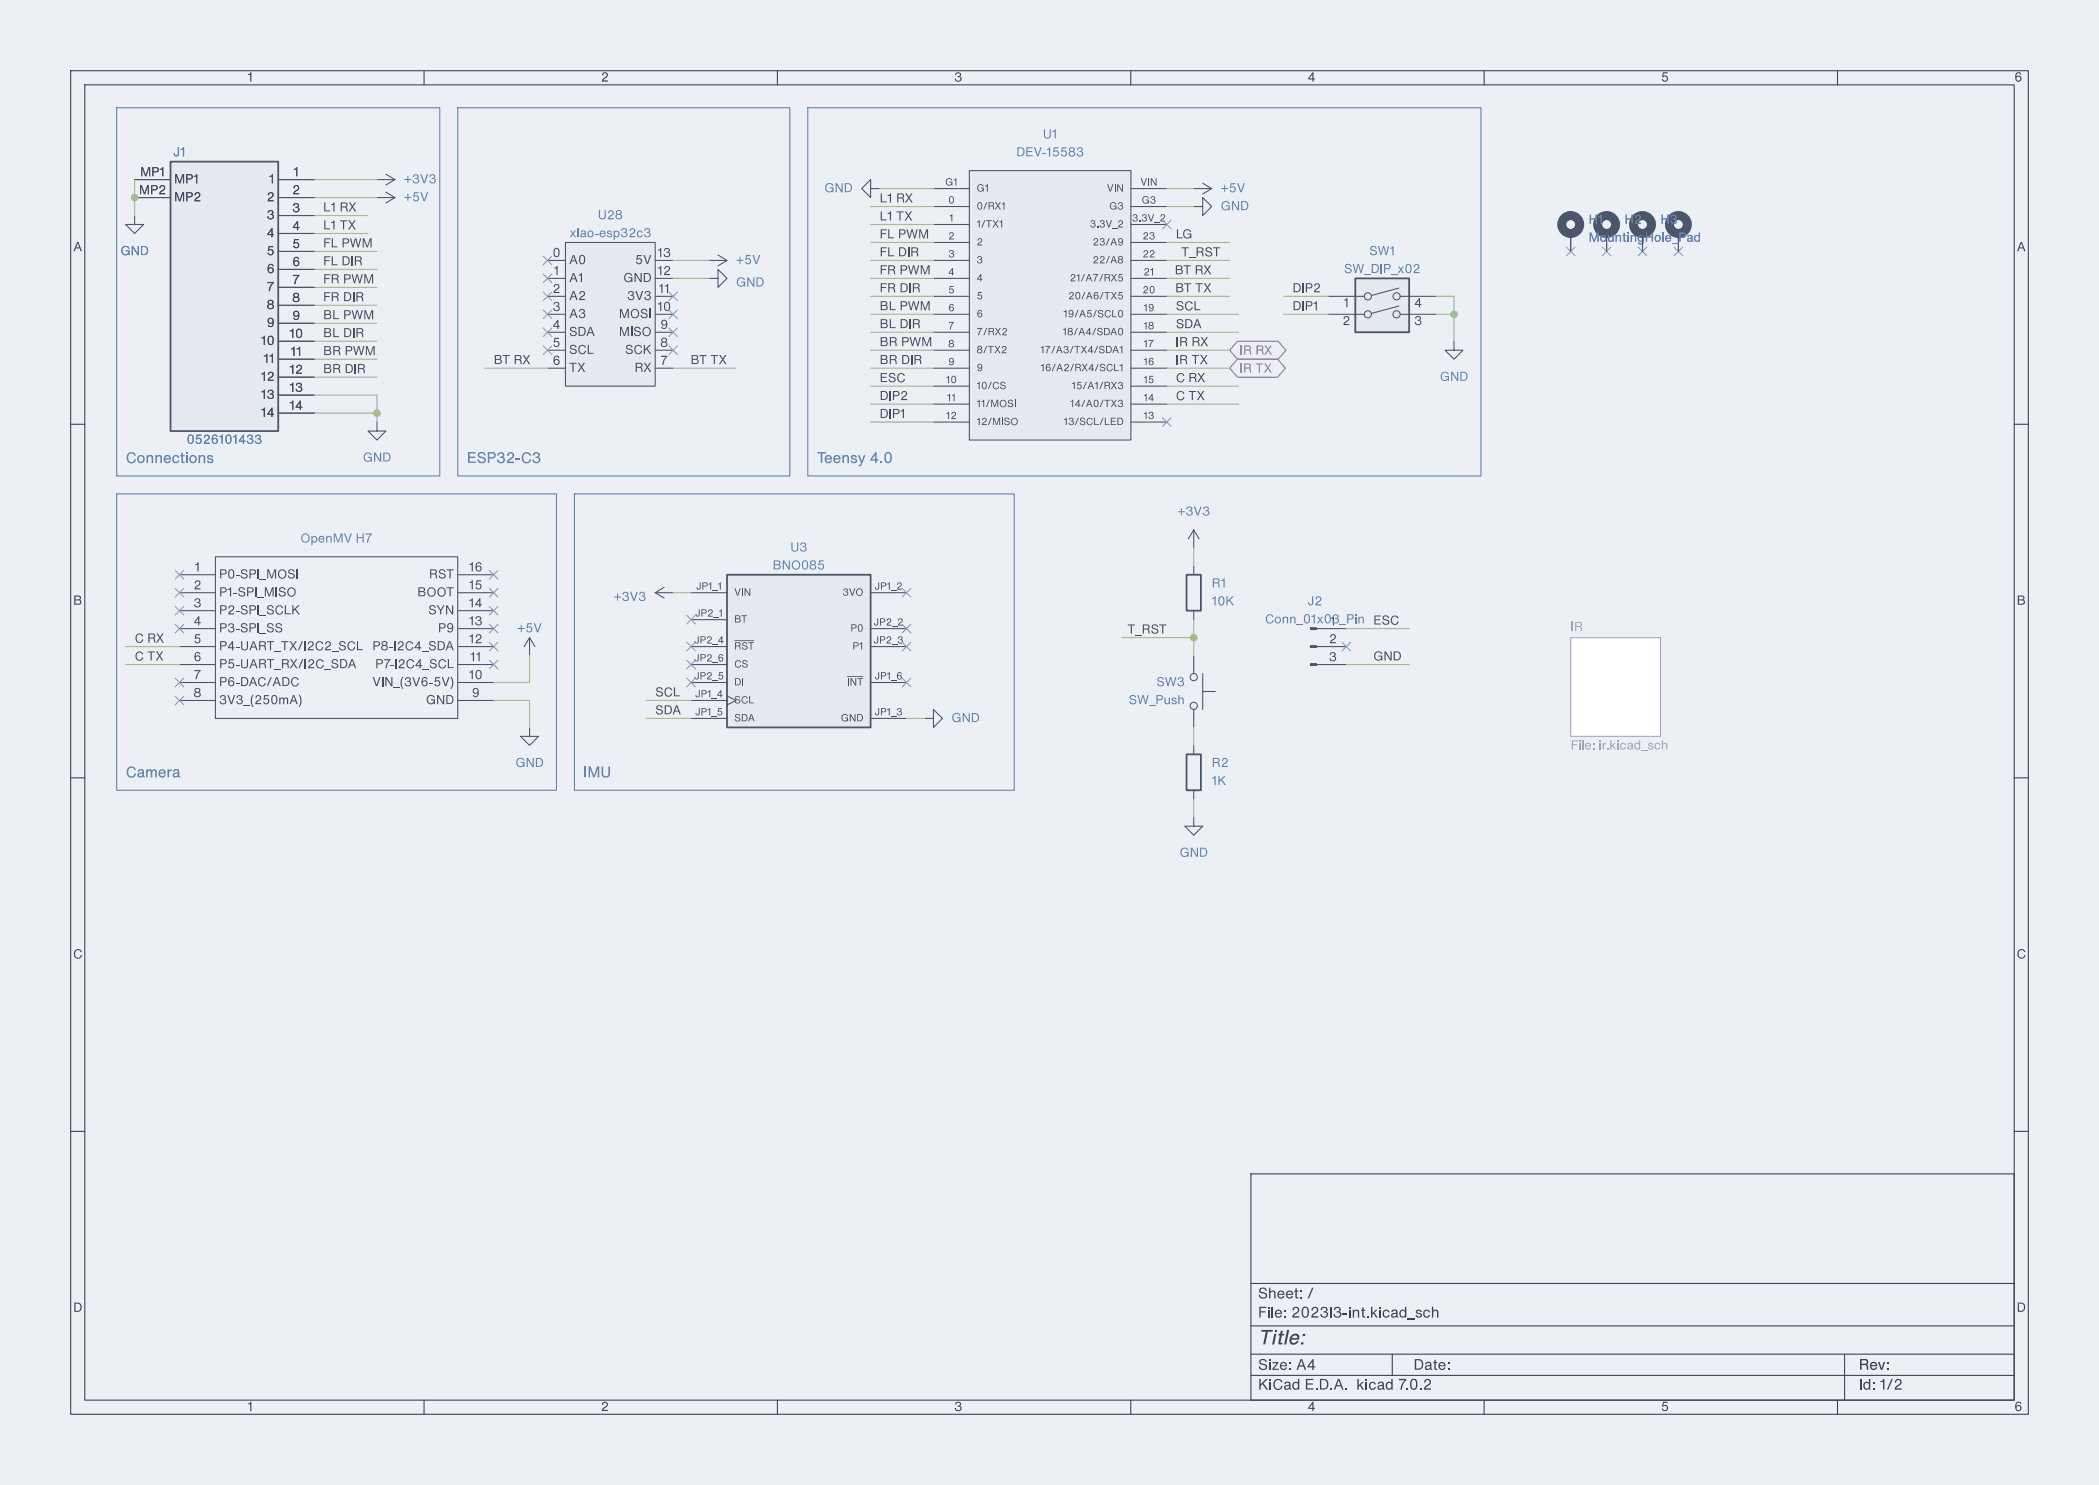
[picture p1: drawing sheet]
<svg xmlns="http://www.w3.org/2000/svg" width="297mm" height="210mm" viewBox="0 0 297 210" stroke-linecap="round" stroke-linejoin="round" font-family="sans-serif">
<defs><g id="words">
<text font-size="2.8" fill="#3b4252" x="178" y="190.8">Title:</text>
<g font-size="2.1" fill="#5e81ac">
<text x="17.8" y="65.7">Connections</text>
<text x="66" y="65.7">ESP32-C3</text>
<text x="115.6" y="65.7">Teensy4.0</text>
<text x="17.8" y="110.2">Camera</text>
<text x="82.5" y="110.2">IMU</text>
</g>
<g font-size="2.1" fill="#3b4252">
<text x="178" y="184.1">Sheet: /</text>
<text x="178" y="186.8">File: 2023l3-int.kicad_sch</text>
<text x="178" y="197">KiCad E.D.A. kicad 7.0.2</text>
<text x="178" y="194.2">Size: A4</text>
<text x="200" y="194.2">Date:</text>
<text x="263" y="194.2">Rev:</text>
<text x="263" y="197">Id: 1/2</text>
</g>
<g font-size="1.8" fill="#3b4252">
<text x="35" y="12">1</text>
<text x="85" y="12">2</text>
<text x="135" y="12">3</text>
<text x="185" y="12">4</text>
<text x="235" y="12">5</text>
<text x="285" y="12">6</text>
<text x="10.3" y="36">A</text>
<text x="285.4" y="36">A</text>
<text x="10.3" y="86">B</text>
<text x="285.3" y="86">B</text>
<text x="10.3" y="136">C</text>
<text x="285.3" y="136">C</text>
<text x="10.4" y="186">D</text>
<text x="285.4" y="186">D</text>
<text x="35" y="200">1</text>
<text x="85" y="200">2</text>
<text x="135" y="200">3</text>
<text x="185" y="200">4</text>
<text x="235" y="200">5</text>
<text x="285" y="200">6</text>
</g>
<g font-size="1.8" fill="#5e81ac">
<text x="24.5" y="22.5">J1</text>
<text x="143.8" y="22.5">DEV-15583</text>
<text x="147.6" y="20">U1</text>
<text x="57.1" y="26.3">+3V3</text>
<text x="57.1" y="28.9">+5V</text>
<text x="116.6" y="27.6">GND</text>
<text x="172.7" y="27.6">+5V</text>
<text x="80.6" y="34">xiao-esp32c3</text>
<text x="84.6" y="31.4">U28</text>
<text x="172.7" y="30.2">GND</text>
<text x="224.8" y="32.1">H1</text>
<text x="229.9" y="32.1">H2</text>
<text x="234.9" y="32.1">H3</text>
<text x="17" y="36.5">GND</text>
<text x="104.1" y="41">GND</text>
<text x="104.1" y="37.8">+5V</text>
<text x="190.2" y="39">SW_DIP_x02</text>
<text x="193.7" y="36.5">SW1</text>
<text x="203.7" y="54.3">GND</text>
<text x="26.4" y="63.2">0526101433</text>
<text x="51.3" y="65.7">GND</text>
<text x="42.5" y="77.1">OpenMV H7</text>
<text x="166.6" y="73.3">+3V3</text>
<text x="109.3" y="81">BNO085</text>
<text x="111.8" y="78.4">U3</text>
<text x="171.4" y="83.5">R1</text>
<text x="73.2" y="89.8">+5V</text>
<text x="86.8" y="85.4">+3V3</text>
<text x="171.4" y="86">10K</text>
<text x="179" y="88.6">Conn_01x03_Pin</text>
<text x="185" y="86">J2</text>
<text x="159.7" y="100">SW_Push</text>
<text x="163.6" y="97.5">SW3</text>
<text x="134.6" y="102.5">GND</text>
<text x="72.9" y="108.9">GND</text>
<text x="171.4" y="108.9">R2</text>
<text x="171.4" y="111.4">1K</text>
<text x="166.9" y="121.6">GND</text>
</g>
<g font-size="1.8" fill="#434c5e">
<text x="19.7" y="27.7">MP2</text>
<text x="19.8" y="25.1">MP1</text>
<text x="24.6" y="26.3">MP1</text>
<text x="24.6" y="28.9">MP2</text>
<text x="37.7" y="28.9">2</text>
<text x="38.1" y="26.3">1</text>
<text x="41.3" y="27.7">2</text>
<text x="41.5" y="25.1">1</text>
<text x="124.5" y="28.9">L1 RX</text>
<text x="37.7" y="31.4">3</text>
<text x="37.7" y="34">4</text>
<text x="41.3" y="30.2">3</text>
<text x="41.3" y="32.8">4</text>
<text x="41.3" y="35.3">5</text>
<text x="45.7" y="32.7">L1 TX</text>
<text x="45.7" y="30.1">L1 RX</text>
<text x="45.7" y="35.2">FL PWM</text>
<text x="124.5" y="33.9">FL PWM</text>
<text x="124.5" y="31.4">L1 TX</text>
<text x="166.4" y="33.9">LG</text>
<text x="37.7" y="36.5">5</text>
<text x="37.7" y="39">6</text>
<text x="37.7" y="41.6">7</text>
<text x="41.3" y="37.8">6</text>
<text x="41.3" y="40.4">7</text>
<text x="45.7" y="37.8">FL DIR</text>
<text x="45.7" y="40.3">FR PWM</text>
<text x="78.2" y="36.6">0</text>
<text x="78.2" y="41.7">2</text>
<text x="78.3" y="39.1">1</text>
<text x="80.5" y="37.8">A0</text>
<text x="80.5" y="40.3">A1</text>
<text x="88.2" y="40.3">GND</text>
<text x="89.9" y="37.8">5V</text>
<text x="93" y="39.1">12</text>
<text x="93" y="36.6">13</text>
<text x="93.2" y="41.7">11</text>
<text x="124.5" y="41.6">FR DIR</text>
<text x="124.5" y="36.5">FL DIR</text>
<text x="124.5" y="39">FR PWM</text>
<text x="166.2" y="39">BT RX</text>
<text x="166.3" y="41.6">BT TX</text>
<text x="167.1" y="36.5">T_RST</text>
<text x="182.9" y="41.6">DIP2</text>
<text x="37.7" y="44.1">8</text>
<text x="37.7" y="46.7">9</text>
<text x="41.3" y="42.9">8</text>
<text x="41.3" y="45.5">9</text>
<text x="45.7" y="42.8">FR DIR</text>
<text x="45.7" y="45.4">BL PWM</text>
<text x="45.7" y="47.9">BL DIR</text>
<text x="78.2" y="44.2">3</text>
<text x="78.2" y="46.7">4</text>
<text x="80.5" y="42.9">A2</text>
<text x="80.5" y="45.4">A3</text>
<text x="80.5" y="47.9">SDA</text>
<text x="87.6" y="45.4">MOSI</text>
<text x="87.6" y="47.9">MISO</text>
<text x="88.7" y="42.9">3V3</text>
<text x="93" y="44.2">10</text>
<text x="93.4" y="46.7">9</text>
<text x="124.5" y="44.1">BL PWM</text>
<text x="124.5" y="46.6">BL DIR</text>
<text x="166.4" y="46.6">SDA</text>
<text x="166.4" y="44.1">SCL</text>
<text x="182.9" y="44.1">DIP1</text>
<text x="36.9" y="49.2">10</text>
<text x="37.3" y="51.7">11</text>
<text x="40.9" y="48">10</text>
<text x="40.9" y="53.1">12</text>
<text x="41.1" y="50.5">11</text>
<text x="45.7" y="53">BR DIR</text>
<text x="45.7" y="50.5">BR PWM</text>
<text x="69.8" y="51.7">BT RX</text>
<text x="78.2" y="49.3">5</text>
<text x="78.2" y="51.8">6</text>
<text x="80.5" y="50.5">SCL</text>
<text x="80.5" y="53">TX</text>
<text x="88.4" y="50.5">SCK</text>
<text x="89.8" y="53">RX</text>
<text x="93.4" y="51.8">7</text>
<text x="93.4" y="49.3">8</text>
<text x="97.7" y="51.7">BT TX</text>
<text x="124.5" y="51.7">BR DIR</text>
<text x="124.5" y="49.2">BR PWM</text>
<text x="166.4" y="51.7">IR TX</text>
<text x="166.4" y="49.2">IR RX</text>
<text x="36.9" y="54.3">12</text>
<text x="36.9" y="56.8">13</text>
<text x="36.9" y="59.4">14</text>
<text x="40.9" y="55.6">13</text>
<text x="40.9" y="58.2">14</text>
<text x="124.5" y="56.8">DIP2</text>
<text x="124.5" y="54.3">ESC</text>
<text x="124.5" y="59.3">DIP1</text>
<text x="166.4" y="54.3">C RX</text>
<text x="166.4" y="56.8">C TX</text>
<text x="27.4" y="83.6">2</text>
<text x="27.5" y="81">1</text>
<text x="31" y="82.2">P0-SPI_MOSI</text>
<text x="60.7" y="82.2">RST</text>
<text x="66.3" y="83.6">15</text>
<text x="66.3" y="81">16</text>
<text x="27.4" y="86.1">3</text>
<text x="27.4" y="88.6">4</text>
<text x="31" y="84.8">P1-SPI_MISO</text>
<text x="31" y="87.3">P2-SPI_SCLK</text>
<text x="31" y="89.8">P3-SPI_SS</text>
<text x="59" y="84.8">BOOT</text>
<text x="60.6" y="87.3">SYN</text>
<text x="62" y="89.8">P9</text>
<text x="66.3" y="88.6">13</text>
<text x="66.3" y="86.1">14</text>
<text x="159.5" y="89.8">T_RST</text>
<text x="188.2" y="88.6">1</text>
<text x="194.3" y="88.6">ESC</text>
<text x="19" y="93.6">C TX</text>
<text x="19" y="91.1">C RX</text>
<text x="27.4" y="91.2">5</text>
<text x="27.4" y="93.7">6</text>
<text x="31" y="92.4">P4-UART_TX/I2C2_SCL</text>
<text x="31" y="94.9">P5-UART_RX/I2C_SDA</text>
<text x="52.7" y="92.4">P8-I2C4_SDA</text>
<text x="53.1" y="94.9">P7-I2C4_SCL</text>
<text x="66.3" y="91.2">12</text>
<text x="66.5" y="93.7">11</text>
<text x="188" y="91.2">2</text>
<text x="188" y="93.7">3</text>
<text x="194.3" y="93.6">GND</text>
<text x="27.4" y="96.3">7</text>
<text x="27.4" y="98.8">8</text>
<text x="31" y="97.5">P6-DAC/ADC</text>
<text x="31" y="100">3V3_(250mA)</text>
<text x="52.7" y="97.5">VIN_(3V6-5V)</text>
<text x="60.3" y="100">GND</text>
<text x="66.3" y="96.3">10</text>
<text x="66.7" y="98.8">9</text>
<text x="92.7" y="101.3">SDA</text>
<text x="92.7" y="98.7">SCL</text>
</g>
<text font-size="1.8" fill="#4c566a" x="224.8" y="34.6">MountingHole_Pad</text>
<g font-size="1.8" fill="#bf616a">
<text x="175.4" y="50.6">IR RX</text>
<text x="175.4" y="53.1">IR TX</text>
</g>
<g font-size="1.8" fill="#b48ead">
<text x="222.2" y="89.5">IR</text>
<text x="222.2" y="106.6">File: ir.kicad_sch</text>
</g>
<g font-size="1.4" fill="#434c5e">
<text x="133.7" y="26.4">G1</text>
<text x="134.2" y="29">0</text>
<text x="138.2" y="27.4">G1</text>
<text x="138.2" y="30">0/RX1</text>
<text x="156.6" y="27.4">VIN</text>
<text x="156.9" y="30">G3</text>
<text x="161.4" y="26.4">VIN</text>
<text x="161.5" y="29">G3</text>
<text x="134.2" y="34">2</text>
<text x="134.3" y="31.5">1</text>
<text x="138.2" y="35">2</text>
<text x="138.2" y="32.5">1/TX1</text>
<text x="154.2" y="32.5">3.3V_2</text>
<text x="154.6" y="35">23/A9</text>
<text x="160.2" y="31.5">3.3V_2</text>
<text x="161.6" y="34">23</text>
<text x="134.2" y="36.6">3</text>
<text x="134.2" y="39.1">4</text>
<text x="134.2" y="41.7">5</text>
<text x="138.2" y="37.6">3</text>
<text x="138.2" y="40.1">4</text>
<text x="151.4" y="40.1">21/A7/RX5</text>
<text x="154.6" y="37.6">22/A8</text>
<text x="161.6" y="41.7">20</text>
<text x="161.6" y="36.6">22</text>
<text x="161.8" y="39.1">21</text>
<text x="134.2" y="44.2">6</text>
<text x="134.2" y="46.7">7</text>
<text x="138.2" y="42.7">5</text>
<text x="138.2" y="45.2">6</text>
<text x="138.2" y="47.7">7/RX2</text>
<text x="150.3" y="47.7">18/A4/SDA0</text>
<text x="150.5" y="45.2">19/A5/SCL0</text>
<text x="151.1" y="42.7">20/A6/TX5</text>
<text x="161.8" y="46.7">18</text>
<text x="161.8" y="44.2">19</text>
<text x="134.2" y="51.8">9</text>
<text x="134.2" y="49.3">8</text>
<text x="138.2" y="52.8">9</text>
<text x="138.2" y="50.3">8/TX2</text>
<text x="147.2" y="50.3">17/A3/TX4/SDA1</text>
<text x="147.2" y="52.8">16/A2/RX4/SCL1</text>
<text x="161.8" y="51.8">16</text>
<text x="161.8" y="49.3">17</text>
<text x="133.8" y="54.4">10</text>
<text x="133.8" y="59.4">12</text>
<text x="134" y="56.9">11</text>
<text x="138.2" y="55.4">10/CS</text>
<text x="138.2" y="57.9">11/MOSI</text>
<text x="151.4" y="57.9">14/A0/TX3</text>
<text x="151.6" y="55.4">15/A1/RX3</text>
<text x="161.8" y="59.4">13</text>
<text x="161.8" y="56.9">14</text>
<text x="161.8" y="54.4">15</text>
<text x="138.2" y="60.4">12/MISO</text>
<text x="150.5" y="60.4">13/SCL/LED</text>
<text x="98.5" y="83.6">JP1_1</text>
<text x="123.7" y="83.6">JP1_2</text>
<text x="98.3" y="87.4">JP2_1</text>
<text x="103.9" y="84.6">VIN</text>
<text x="103.9" y="88.4">BT</text>
<text x="119.2" y="84.6">3VO</text>
<text x="120.3" y="89.7">P0</text>
<text x="123.6" y="88.6">JP2_2</text>
<text x="98.2" y="91.2">JP2_4</text>
<text x="98.2" y="93.7">JP2_6</text>
<text x="103.9" y="94.7">CS</text>
<text x="120.6" y="92.2">P1</text>
<text x="123.6" y="91.2">JP2_3</text>
<text x="98.2" y="96.3">JP2_5</text>
<text x="98.3" y="98.8">JP1_4</text>
<text x="98.3" y="101.3">JP1_5</text>
<text x="103.9" y="99.8">SCL</text>
<text x="103.9" y="97.3">DI</text>
<text x="123.7" y="101.3">JP1_3</text>
<text x="123.7" y="96.3">JP1_6</text>
<text x="103.9" y="102.4">SDA</text>
<text x="119" y="102.4">GND</text>
</g>
</g></defs>
<path d="M0 0h297v210h-297z" fill="#eceff4" stroke="#eceff4" stroke-width=".14"/>
<g fill="none" stroke="#3b4252" stroke-width=".15">
<path d="M10 10h277v190h-277zM12 12h273v186h-273zM60 10v2M110 10v2M160 10v2M210 10v2M260 10v2M10 60h2M285 60h2M10 110h2M285 110h2M10 160h2"/>
<path d="M285 160h2M177 166h108v32h-108zM60 198v2M110 198v2M160 198v2M177 194.5h108M177 191.5h108M177 187.5h108M210 198v2M260 198v2"/>
</g>
<g fill="#3b4252">
<path d="M201.5 185.3l.4-.1 .4 .2v.2h-.1l-.1-.2h-.3l-.1 .1-.1 .2v.3l.2 .2h.2l.2-.3h.1l-.2 .4h-.3l-.3-.2-.1-.4z"/>
<path d="M202.6 184.8h.2v.6l.4-.2 .3 .2v.9h-.2v-.8l-.2-.1-.3 .2v.7h-.2z"/>
</g>
<path d="M177 181.5h108M197 191.5v3M261 191.5v6.5" fill="none" stroke="#3b4252" stroke-width=".15"/>
<path d="M222.2 90.2h12.7v13.9h-12.7z" fill="#fff" stroke="#fff" stroke-width=".14"/>
<path d="M222.2 90.2h12.7v13.9h-12.7z" fill="none" stroke="#b48ead" stroke-width=".15"/>
<g fill="#b48ead">
<path d="M222.4 104.7h.9v.1h-.7v.4h.6v.2h-.6v.6h-.2z"/>
<path d="M223.4 104.7h.2v.2h-.2z"/>
<path d="M223.9 104.7h.1v1.3h-.1z"/>
<path d="M226.3 104.7h.2v.2h-.2z"/>
<path d="M227.9 104.7h.1v.8l.4-.4h.2l-.3 .3 .4 .6h-.2l-.3-.5-.2 .1v.4h-.1z"/>
<path d="M228.9 104.7h.1v.2h-.1z"/>
<path d="M231.4 105.1l.3-.1 .2 .2v-.5h.2v1.3h-.2v-.2l-.2 .2-.3-.1-.2-.4h.2l.1 .3 .1 .1 .2-.1 .1-.3v-.2l-.2-.1-.2 .1-.1 .2h-.2z"/>
<path d="M235.1 104.7h.2v.5l.3-.2 .3 .2v.8h-.1v-.7l-.2-.1-.3 .1v.7h-.2z"/>
</g>
<path d="M137.2 24.1h22.8v38.1h-22.8z" fill="#e5e9f0" stroke="#e5e9f0" stroke-width=".14"/>
<g fill="none" stroke="#4c566a" stroke-width=".15">
<path d="M132.1 34.3h5.1M132.1 36.8h5.1M132.1 31.8h5.1M132.1 39.4h5.1M132.1 26.7h5.1M132.1 29.2h5.1M137.2 24.1h22.8v38.1h-22.8zM160 31.8h5.1M160 26.7h5.1M160 29.2h5.1M132.1 41.9h5.1M132.1 44.5h5.1"/>
<path d="M132.1 52.1h5.1M132.1 54.6h5.1M132.1 57.2h5.1M132.1 59.7h5.1M160 59.7h5.1"/>
</g>
<path d="M158.1 59.1h.5l.2 .1 .1 .5-.2 .3-.6 .1v-.9h.1v.8l.5-.1 .1-.3-.1-.3-.6-.1z" fill="#434c5e"/>
<path d="M160 57.2h5.1" fill="none" stroke="#4c566a" stroke-width=".15"/>
<path d="M158.3 56.6l.3-.1 .2 .2 .1 .2-.2 .1 .2 .1v.2l-.2 .2-.3 .1-.2-.2v-.2h.1l.2 .3 .2-.1 .1-.1-.1-.2h-.2v-.1l.2-.1v-.2h-.2l-.2 .1h-.1z" fill="#434c5e"/>
<path d="M160 54.6h5.1" fill="none" stroke="#4c566a" stroke-width=".15"/>
<path d="M158.3 54.1l.3-.1 .2 .1 .1 .2-.2 .2 .2 .1v.2l-.2 .2h-.3l-.2-.1v-.2h.1l.2 .2h.2l.1-.1-.1-.2-.2-.1v-.1h.2v-.2l-.2-.1-.2 .2h-.1z" fill="#434c5e"/>
<path d="M160 52.1h5.1" fill="none" stroke="#4c566a" stroke-width=".15"/>
<g fill="#434c5e">
<path d="M157.6 51.5h.2v.9h.5v.1h-.7z"/>
<path d="M158.4 51.6l.4-.1v1h-.1v-.8h-.3z"/>
</g>
<path d="M160 49.5h5.1" fill="none" stroke="#4c566a" stroke-width=".15"/>
<g fill="#434c5e">
<path d="M157.8 48.9h.1l.4 1h-.1l-.1-.3h-.5l-.1 .3h-.1l.2-.4h.4l-.1-.5-.2 .5h-.1z"/>
<path d="M158.4 49.1l.4-.2v1.1h-.1v-.8h-.3z"/>
</g>
<path d="M160 47h5.1" fill="none" stroke="#4c566a" stroke-width=".15"/>
<path d="M158.3 46.4h.3l.3 .2v.5l-.2 .3-.4-.1-.1-.4h.1l.1 .4h.3l.1-.3-.1-.4-.1-.1h-.1l-.2 .4h-.1z" fill="#434c5e"/>
<path d="M160 44.5h5.1" fill="none" stroke="#4c566a" stroke-width=".15"/>
<path d="M158.3 43.9l.3-.1 .3 .2v.6l-.2 .3-.4-.1-.1-.4h.1l.1 .3 .3 .1 .1-.3-.1-.4-.2-.1-.2 .4h-.1z" fill="#434c5e"/>
<path d="M160 41.9h5.1" fill="none" stroke="#4c566a" stroke-width=".15"/>
<path d="M158.3 41.3h.5v.1h-.4v.3h.2l.3 .1v.3l-.2 .2h-.3l-.2-.2h.1l.1 .1h.2l.2-.1-.2-.3h-.4z" fill="#434c5e"/>
<path d="M160 39.4h5.1" fill="none" stroke="#4c566a" stroke-width=".15"/>
<path d="M158.3 38.8h.5v.1h-.4v.3l.2-.1 .3 .2v.3l-.2 .2h-.3l-.2-.2v-.1h.1l.1 .2h.2l.2-.2-.2-.3-.4 .1z" fill="#434c5e"/>
<path d="M160 36.8h5.1" fill="none" stroke="#4c566a" stroke-width=".15"/>
<path d="M158.3 36.3l.3-.1 .2 .1 .1 .3-.2 .1 .2 .3-.1 .2-.4 .1-.2-.2v-.1l.3 .2 .3-.2-.1-.2h-.1l-.4 .2 .2-.3-.2-.2 .3 .1 .2-.1v-.1l-.1-.1-.4 .2z" fill="#434c5e"/>
<path d="M160 34.3h5.1" fill="none" stroke="#4c566a" stroke-width=".15"/>
<path d="M158.3 33.8l.3-.1 .3 .2v.5l-.2 .3h-.3l-.2-.2 .4 .1 .2-.4-.4 .1-.2-.3 .4 .2 .1-.1v-.2l-.2-.1-.2 .2h-.1z" fill="#434c5e"/>
<path d="M132.1 47h5.1M132.1 49.5h5.1" fill="none" stroke="#4c566a" stroke-width=".15"/>
<path d="M141.9 49l.3-.1 .2 .2v.3l-.5 .4h.5v.2h-.6v-.3l.5-.5-.1-.1-.1-.1-.2 .1v.2h-.1z" fill="#434c5e"/>
<g fill="none" stroke="#4c566a" stroke-width=".15">
<path d="M19 30.5v1.3h1.3l-1.3 1.2-1.2-1.2h1.2M19 25.4h5.1M19 27.9h5.1M39.4 25.4h5M39.4 27.9h5M39.4 30.5h5M39.4 33h5M39.4 35.6h5M39.4 38.1h5M53.3 25.4h2.6M53.3 27.9h2.6M54.6 24.6l1.3 .8"/>
<path d="M54.6 27.2l1.3 .7M55.9 25.4l-1.3 .8M55.9 27.9l-1.3 .8M100.3 39.4h1.3v-1.3l1.3 1.3-1.3 1.2v-1.2M39.4 48.3h5M39.4 50.8h5M39.4 53.3h5M39.4 55.9h5M39.4 58.4h5M39.4 40.6h5M39.4 43.2h5M39.4 45.7h5"/>
<path d="M168.9 74.9l.8 1.3M168.9 74.9v2.6M168.9 74.9l-.8 1.3M74.9 90.2l-.7 1.2M74.9 90.2v2.5M74.9 90.2l.8 1.2M92.7 83.8l1.3 .8M92.7 83.8h2.5M94 83.1l-1.3 .7M186.3 94h4.2M186.3 91.4h4.2M186.7 88.9h3.8"/>
<path d="M168.9 115.6v1.2h-1.3l1.3 1.3 1.3-1.3h-1.3"/>
</g>
<circle cx="237.5" cy="31.7" r="1.27" fill="none" stroke="#4c566a" stroke-width="1.3"/>
<g fill="#4c566a" stroke="#4c566a" stroke-width=".15">
<path d="M185.4 93.9h.9v.2h-.9z"/>
<path d="M185.4 91.3h.9v.3h-.9z"/>
</g>
<path d="M24.1 22.9h15.3v38.1h-15.3z" fill="#e5e9f0" stroke="#e5e9f0" stroke-width=".14"/>
<path d="M24.1 22.9h15.3v38.1h-15.3z" fill="none" stroke="#4c566a" stroke-width=".25"/>
<path d="M36.2 61.6l.4-.1 .3 .1v.3l-.1 .2 .1 .1 .1 .2-.2 .3-.4 .1-.3-.2v-.3h.1l.1 .3h.2h.2l.1-.2-.1-.2-.3-.1v-.1l.3-.1v-.2l-.3-.1-.1 .3h-.2z" fill="#5e81ac"/>
<path d="M102.9 81.3h20.3v21.6h-20.3z" fill="#e5e9f0" stroke="#e5e9f0" stroke-width=".14"/>
<path d="M102.9 81.3h20.3v21.6h-20.3z" fill="none" stroke="#4c566a" stroke-width=".25"/>
<path d="M97.8 83.8h5.1M97.8 99.1h5.1M102.9 98.4l1.2 .7-1.2 .6M123.2 83.8h5.1M123.2 96.5h5.1M97.8 101.6h5.1M123.2 101.6h5.1" fill="none" stroke="#4c566a" stroke-width=".15"/>
<g fill="#434c5e">
<path d="M120 95.9h.1v1h-.1z"/>
<path d="M120.3 95.9h.2l.5 .9v-.9h.2v1h-.2l-.5-.8v.8h-.2z"/>
<path d="M121.3 95.9h.8v.1h-.3v.9h-.2v-.9h-.3z"/>
<path d="M119.9 95.6l2.3 .1h-2.3z"/>
</g>
<path d="M97.8 87.6h5.1M97.8 91.4h5.1M123.2 88.9h5.1M123.2 91.4h5.1" fill="none" stroke="#4c566a" stroke-width=".15"/>
<g fill="#434c5e">
<path d="M104 90.8h.5l.2 .1 .1 .3-.2 .1 .2 .2v.4h-.1l-.1-.4-.1-.1h-.4v.5h-.1v-1h.1v.4h.4l.2-.2-.1-.1-.6-.1z"/>
<path d="M105.1 90.9l.3-.1 .3 .2v.1l-.3-.2-.3 .2 .1 .1 .5 .2 .1 .2-.1 .2-.4 .1-.3-.2v-.2h.1l.1 .2 .1 .1 .3-.1 .1-.1-.1-.2-.5-.1z"/>
<path d="M105.9 90.8h.8v.1h-.4v1h-.1v-1h-.3z"/>
<path d="M103.9 90.6h2.8l-2.8 .1z"/>
</g>
<g fill="none" stroke="#4c566a" stroke-width=".15">
<path d="M77.5 36.8h2.5M77.5 39.4h2.5M80 34.3h12.7v20.3h-12.7zM100.3 36.8h2.6M101.6 36.1l1.3 .7M102.9 36.8l-1.3 .8M77.5 41.9h2.5M77.5 44.5h2.5M77.5 47h2.5M77.5 49.5h2.5M77.5 52.1h2.5M92.7 41.9h2.5"/>
<path d="M92.7 47h2.5M92.7 49.5h2.5M92.7 52.1h2.5M97.8 96.5h5.1M97.8 94h5.1M130.8 101.6h1.3v-1.3l1.2 1.3-1.2 1.3v-1.3"/>
</g>
<path d="M80 34.3h12.7v20.3h-12.7z" fill="#e5e9f0" stroke="#e5e9f0" stroke-width=".14"/>
<path d="M91.3 32.4l.3-.1 .4 .1v.3l-.2 .2 .2 .1 .1 .2-.3 .3-.4 .1-.2-.2-.1-.3h.2l.1 .2 .1 .1h.3l.1-.2-.1-.2-.3-.1v-.1l.3-.1v-.2l-.3-.1-.2 .2h-.1z" fill="#5e81ac"/>
<path d="M191.8 39.4h7.6v7.6h-7.6zM167.9 81.3h2v5.1h-2zM167.9 106.7h2v5.1h-2z" fill="none" stroke="#4c566a" stroke-width=".25"/>
<g fill="none" stroke="#4c566a" stroke-width=".15">
<path d="M168.9 29.2h1.3v-1.3l1.2 1.3-1.2 1.3v-1.3M188 41.9h5M197.9 43.3l-3.8 1M197.9 40.7l-3.8 1.1M205.7 48.3v1.2h1.3l-1.3 1.3-1.2-1.3h1.2M168.9 80v1.3M168.9 86.4v1.2M168.9 92.7v2.6M170.2 97.8h1.8M170.2 95.3v5M74.9 102.9v1.2h1.3l-1.3 1.3-1.2-1.3h1.2M168.9 100.3v2.6"/>
<path d="M168.9 105.4v1.3M168.9 111.8v1.2"/>
<circle cx="193.5" cy="44.5" r=".51"/>
<circle cx="193.5" cy="41.9" r=".51"/>
<circle cx="197.6" cy="44.5" r=".51"/>
<circle cx="197.6" cy="41.9" r=".51"/>
<circle cx="168.9" cy="99.8" r=".51"/>
<circle cx="168.9" cy="95.8" r=".51"/>
</g>
<path d="M191.8 39.4h7.6v7.6h-7.6z" fill="#e5e9f0" stroke="#e5e9f0" stroke-width=".14"/>
<path d="M190.2 42.4l.5-.3v1.3h-.2v-.9h-.3z" fill="#434c5e"/>
<path d="M188 44.5h5" fill="none" stroke="#4c566a" stroke-width=".15"/>
<path d="M190.2 44.8l.4-.1 .3 .2v.4l-.6 .5h.6v.2h-.8l.1-.4 .6-.5-.1-.2-.2-.1-.2 .1v.2h-.2z" fill="#434c5e"/>
<path d="M198.1 44.5h5.1" fill="none" stroke="#4c566a" stroke-width=".15"/>
<path d="M200.3 44.8l.4-.1 .3 .2v.2l-.1 .2 .2 .1v.2l-.2 .3-.4 .1-.3-.2v-.2h.2v.2l.2 .1 .3-.1 .1-.2-.1-.2h-.3v-.2l.3-.1v-.2l-.4-.1-.1 .3h-.2z" fill="#434c5e"/>
<path d="M198.1 41.9h5.1" fill="none" stroke="#4c566a" stroke-width=".15"/>
<path d="M200.8 42.1h.1v.9h.2v.1h-.2v.3h-.1v-.3h-.6v-.1h.6v-.6l-.4 .6h-.2z" fill="#434c5e"/>
<g fill="none" stroke="#4c566a" stroke-width=".15">
<path d="M168.9 26.7h2.5M170.2 25.9l1.2 .8M171.4 26.7l-1.2 .7M30.5 78.7h34.3v22.9h-34.3zM25.4 81.3h5.1M25.4 91.4h5.1M25.4 88.9h5.1M25.4 86.4h5.1M25.4 83.8h5.1M64.8 81.3h5M64.8 96.5h5M64.8 94h5"/>
<path d="M64.8 91.4h5M64.8 88.9h5M64.8 86.4h5M64.8 83.8h5"/>
</g>
<path d="M50.5 90.7h.2v1.1h.6v.1h-.8z" fill="#434c5e"/>
<path d="M25.4 94h5.1M25.4 96.5h5.1" fill="none" stroke="#4c566a" stroke-width=".15"/>
<path d="M41.4 95.9l.4-.1 .4 .2 .1 .2h-.2l-.2-.3h-.3l-.2 .4v.4l.2 .2h.3l.2-.3h.2l-.3 .4-.4 .1-.3-.3-.1-.5z" fill="#434c5e"/>
<path d="M25.4 99.1h5.1" fill="none" stroke="#4c566a" stroke-width=".15"/>
<path d="M42.3 98.2h.1l.1 .2 .2 .6-.1 .5-.2 .5h-.1l.2-.5v-.5z" fill="#434c5e"/>
<path d="M222.2 33v2.6M64.8 99.1h5" fill="none" stroke="#4c566a" stroke-width=".15"/>
<g fill="none" stroke="#4c566a" stroke-width="1.3">
<circle cx="222.2" cy="31.7" r="1.27"/>
<circle cx="227.3" cy="31.7" r="1.27"/>
</g>
<path d="M239.8 33.3l.3-.1 .3 .2v-.5h.1v1.3h-.1v-.2l-.3 .2-.3-.1-.1-.4h.2v.3l.2 .1 .2-.1 .1-.3-.1-.2-.2-.1h-.2v.3h-.2z" fill="#5e81ac"/>
<circle cx="232.4" cy="31.7" r="1.27" fill="none" stroke="#4c566a" stroke-width="1.3"/>
<path d="M123.2 26.7v1.2l-1.3-1.2 1.3-1.3v1.3h1.3M53.3 59.7v1.3h1.3l-1.3 1.2-1.2-1.2h1.2" fill="none" stroke="#4c566a" stroke-width=".15"/>
<path d="M175.1 48.3h5.7l1.2 1.2-1.2 1.3h-5.7l-1.1-1.3zM175.1 50.8h5.7l1.1 1.3-1.1 1.2h-5.7l-1.1-1.2z" fill="none" stroke="#bf616a" stroke-width=".15"/>
<path d="M16.5 15.2h45.7v52.1h-45.7zM64.8 15.2h47v52.1h-47zM114.3 15.2h95.2v52.1h-95.2zM16.5 69.9h62.2v41.9h-62.2zM81.3 69.9h62.2v41.9h-62.2z" fill="none" stroke="#5e81ac" stroke-width=".15"/>
<g fill="none" stroke="#a3be8c" stroke-width=".15">
<path d="M19 25.4v5.1M44.4 30.5h7.7M44.4 33h7.7M44.4 25.4h8.9M44.4 27.9h8.9M44.4 35.6h8.9M44.4 38.1h8.9M95.2 39.4h5.1M95.2 36.8h5.1M123.2 39.4h8.9M123.2 29.2h8.9M123.2 36.8h8.9"/>
<path d="M123.2 34.3h8.9M123.2 31.8h8.9M124.5 26.7h7.6M165.1 39.4h8.9M165.1 29.2h3.8M165.1 26.7h3.8M165.1 36.8h8.9M165.1 34.3h8.9M44.4 45.7h8.9M44.4 58.4h8.9M44.4 40.6h8.9M44.4 55.9h8.9v3.8"/>
<path d="M44.4 50.8h8.9M44.4 48.3h8.9M44.4 43.2h8.9M44.4 53.3h8.9M68.6 52.1h8.9M95.2 52.1h8.9M123.2 41.9h8.9M123.2 44.5h8.9M123.2 52.1h8.9M123.2 54.6h8.9M123.2 57.2h8.9M123.2 47h8.9"/>
<path d="M123.2 49.5h8.9M123.2 59.7h8.9M165.1 41.9h8.9M165.1 44.5h10.2M165.1 52.1h8.9M165.1 54.6h10.2M165.1 57.2h10.2M165.1 47h10.2M165.1 49.5h8.9M181.6 41.9h6.4M181.6 44.5h6.4M203.2 41.9h2.5v6.4"/>
<path d="M203.2 44.5h2.5M168.9 77.5v2.5M17.8 94h7.6M17.8 91.4h7.6M69.8 99.1h5.1v3.8M74.9 92.7v3.8h-5.1M91.4 99.1h6.4M95.2 83.8h2.6M158.7 90.2h10.2M168.9 87.6v5.1M190.5 94h8.9M190.5 88.9h8.9"/>
<path d="M91.4 101.6h6.4M128.3 101.6h2.5M168.9 102.9v2.5M168.9 113v2.6"/>
</g>
<g fill="none" stroke="#81a1c1" stroke-width=".15">
<path d="M76.9 38.8l1.2 1.2M76.9 36.2l1.2 1.2M78.1 38.8l-1.2 1.2M78.1 36.2l-1.2 1.2M164.5 31.1l1.2 1.3M165.7 31.1l-1.2 1.3M221.6 35l1.3 1.2M222.9 35l-1.3 1.2M226.7 35l1.2 1.2M227.9 35l-1.2 1.2M231.8 35l1.2 1.2M233 35l-1.2 1.2"/>
<path d="M236.9 35l1.2 1.2M238.1 35l-1.2 1.2M76.9 41.3l1.2 1.2M76.9 46.4l1.2 1.2M76.9 48.9l1.2 1.2M76.9 43.8l1.2 1.3M78.1 41.3l-1.2 1.2M78.1 46.4l-1.2 1.2M78.1 43.8l-1.2 1.3M78.1 48.9l-1.2 1.2M94.6 41.3l1.3 1.2M94.6 48.9l1.3 1.2"/>
<path d="M94.6 43.8l1.3 1.3M94.6 46.4l1.3 1.2M95.9 41.3l-1.3 1.2M95.9 48.9l-1.3 1.2M95.9 43.8l-1.3 1.3M95.9 46.4l-1.3 1.2M164.5 59.1l1.2 1.2M165.7 59.1l-1.2 1.2M24.8 98.5l1.2 1.2M24.8 95.9l1.2 1.2M24.8 88.3l1.2 1.2M24.8 83.2l1.2 1.2"/>
<path d="M24.8 85.8l1.2 1.2M24.8 80.7l1.2 1.2M26 88.3l-1.2 1.2M26 98.5l-1.2 1.2M26 95.9l-1.2 1.2M26 83.2l-1.2 1.2M26 85.8l-1.2 1.2M26 80.7l-1.2 1.2M69.2 90.8l1.3 1.2M69.2 88.3l1.3 1.2M69.2 85.8l1.3 1.2M69.2 83.2l1.3 1.2"/>
<path d="M69.2 80.7l1.3 1.2M69.2 93.4l1.3 1.2M70.5 90.8l-1.3 1.2M70.5 88.3l-1.3 1.2M70.5 85.8l-1.3 1.2M70.5 83.2l-1.3 1.2M70.5 80.7l-1.3 1.2M70.5 93.4l-1.3 1.2M97.2 93.4l1.2 1.2M97.2 95.9l1.2 1.2M97.2 87l1.2 1.2M97.2 90.8l1.2 1.2"/>
<path d="M98.4 93.4l-1.2 1.2M98.4 95.9l-1.2 1.2M98.4 87l-1.2 1.2M98.4 90.8l-1.2 1.2M127.7 95.9l1.2 1.2M127.7 90.8l1.2 1.2M127.7 83.2l1.2 1.2M127.7 88.3l1.2 1.2M128.9 95.9l-1.2 1.2M128.9 90.8l-1.2 1.2M128.9 83.2l-1.2 1.2M128.9 88.3l-1.2 1.2"/>
<path d="M189.9 90.8l1.2 1.2M191.1 90.8l-1.2 1.2"/>
</g>
<path d="M239.8 33.3l.3-.1 .3 .2v-.5h.1v1.3h-.1v-.2l-.3 .2-.3-.1-.1-.4h.2v.3l.2 .1 .2-.1 .1-.3-.1-.2-.2-.1h-.2v.3h-.2z" fill="#5e81ac"/>
<path d="M222.2 33v2.6" fill="none" stroke="#4c566a" stroke-width=".15"/>
<path d="M36.2 61.6l.4-.1 .3 .1v.3l-.1 .2 .1 .1 .1 .2-.2 .3-.4 .1-.3-.2v-.3h.1l.1 .3h.2h.2l.1-.2-.1-.2-.3-.1v-.1l.3-.1v-.2l-.3-.1-.1 .3h-.2z" fill="#5e81ac"/>
<g fill="none" stroke="#4c566a" stroke-width=".15">
<path d="M19 25.4h5.1M19 27.9h5.1M39.4 25.4h5M39.4 27.9h5M39.4 30.5h5M39.4 33h5M39.4 35.6h5M39.4 38.1h5M39.4 48.3h5M39.4 50.8h5M39.4 53.3h5M39.4 55.9h5"/>
<path d="M39.4 58.4h5M39.4 40.6h5M39.4 43.2h5M39.4 45.7h5"/>
</g>
<g fill="#a3be8c" stroke="#a3be8c" stroke-width=".15">
<circle cx="168.9" cy="90.2" r=".46"/>
<circle cx="205.7" cy="44.5" r=".46"/>
<circle cx="19" cy="27.9" r=".46"/>
<circle cx="53.3" cy="58.4" r=".46"/>
</g>
<use href="#words"/>
</svg>
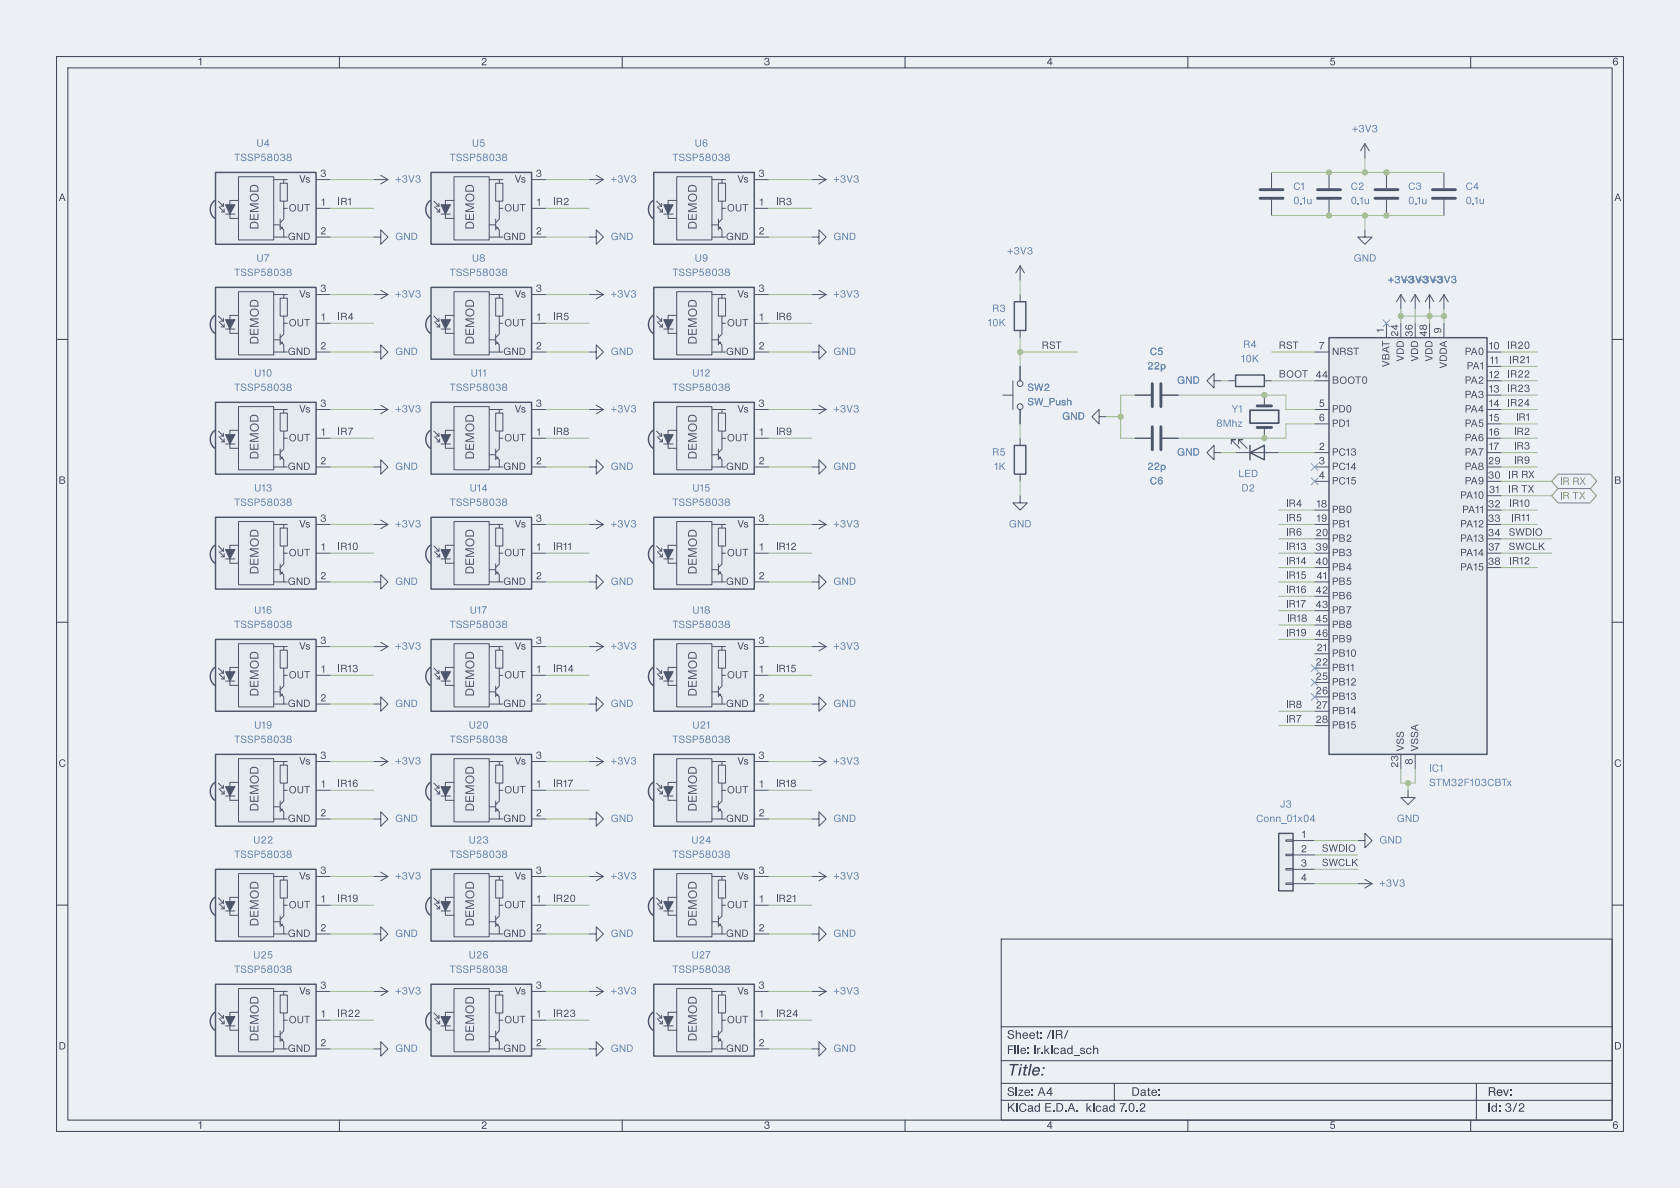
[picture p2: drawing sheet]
<svg xmlns="http://www.w3.org/2000/svg" width="297mm" height="210mm" viewBox="0 0 297 210" stroke-linecap="round" stroke-linejoin="round" font-family="sans-serif">
<defs><g id="words">
<text font-size="2.8" fill="#3b4252" x="178" y="190.8">Title:</text>
<g font-size="2.1" fill="#4c566a">
<text x="46.2" y="40.6" transform="rotate(-90 46.2 40.6)">DEMOD</text>
<text x="84.3" y="40.6" transform="rotate(-90 84.3 40.6)">DEMOD</text>
<text x="123.7" y="40.6" transform="rotate(-90 123.7 40.6)">DEMOD</text>
<text x="46.2" y="60.9" transform="rotate(-90 46.2 60.9)">DEMOD</text>
<text x="84.3" y="60.9" transform="rotate(-90 84.3 60.9)">DEMOD</text>
<text x="123.7" y="60.9" transform="rotate(-90 123.7 60.9)">DEMOD</text>
<text x="46.2" y="81.2" transform="rotate(-90 46.2 81.2)">DEMOD</text>
<text x="84.3" y="81.2" transform="rotate(-90 84.3 81.2)">DEMOD</text>
<text x="123.7" y="81.2" transform="rotate(-90 123.7 81.2)">DEMOD</text>
<text x="46.2" y="101.6" transform="rotate(-90 46.2 101.6)">DEMOD</text>
<text x="84.3" y="101.6" transform="rotate(-90 84.3 101.6)">DEMOD</text>
<text x="123.7" y="101.6" transform="rotate(-90 123.7 101.6)">DEMOD</text>
<text x="46.2" y="123.1" transform="rotate(-90 46.2 123.1)">DEMOD</text>
<text x="84.3" y="123.1" transform="rotate(-90 84.3 123.1)">DEMOD</text>
<text x="123.7" y="123.1" transform="rotate(-90 123.7 123.1)">DEMOD</text>
<text x="46.2" y="143.5" transform="rotate(-90 46.2 143.5)">DEMOD</text>
<text x="84.3" y="143.5" transform="rotate(-90 84.3 143.5)">DEMOD</text>
<text x="123.7" y="143.5" transform="rotate(-90 123.7 143.5)">DEMOD</text>
<text x="46.2" y="163.8" transform="rotate(-90 46.2 163.8)">DEMOD</text>
<text x="84.3" y="163.8" transform="rotate(-90 84.3 163.8)">DEMOD</text>
<text x="123.7" y="163.8" transform="rotate(-90 123.7 163.8)">DEMOD</text>
<text x="46.2" y="184.1" transform="rotate(-90 46.2 184.1)">DEMOD</text>
<text x="84.3" y="184.1" transform="rotate(-90 84.3 184.1)">DEMOD</text>
<text x="123.7" y="184.1" transform="rotate(-90 123.7 184.1)">DEMOD</text>
</g>
<g font-size="2.1" fill="#3b4252">
<text x="178" y="184.1">Sheet: /IR/</text>
<text x="178" y="186.8">File: ir.kicad_sch</text>
<text x="178" y="197">KiCad E.D.A. kicad 7.0.2</text>
<text x="178" y="194.2">Size: A4</text>
<text x="200" y="194.2">Date:</text>
<text x="263" y="194.2">Rev:</text>
<text x="263" y="197">Id: 3/2</text>
</g>
<g font-size="1.8" fill="#3b4252">
<text x="35" y="12">1</text>
<text x="85" y="12">2</text>
<text x="135" y="12">3</text>
<text x="185" y="12">4</text>
<text x="235" y="12">5</text>
<text x="285" y="12">6</text>
<text x="10.3" y="36">A</text>
<text x="285.4" y="36">A</text>
<text x="10.3" y="86">B</text>
<text x="285.3" y="86">B</text>
<text x="10.3" y="136">C</text>
<text x="285.3" y="136">C</text>
<text x="10.4" y="186">D</text>
<text x="285.4" y="186">D</text>
<text x="35" y="200">1</text>
<text x="85" y="200">2</text>
<text x="135" y="200">3</text>
<text x="185" y="200">4</text>
<text x="235" y="200">5</text>
<text x="285" y="200">6</text>
</g>
<g font-size="1.8" fill="#5e81ac">
<text x="239" y="23.8">+3V3</text>
<text x="41.4" y="28.9">TSSP58038</text>
<text x="45.3" y="26.3">U4</text>
<text x="79.5" y="28.9">TSSP58038</text>
<text x="83.4" y="26.3">U5</text>
<text x="118.8" y="28.9">TSSP58038</text>
<text x="122.8" y="26.3">U6</text>
<text x="69.8" y="32.7">+3V3</text>
<text x="107.9" y="32.7">+3V3</text>
<text x="147.3" y="32.7">+3V3</text>
<text x="228.6" y="34">C1</text>
<text x="238.8" y="34">C2</text>
<text x="248.9" y="34">C3</text>
<text x="259.1" y="34">C4</text>
<text x="228.6" y="36.5">0.1u</text>
<text x="238.8" y="36.5">0.1u</text>
<text x="248.9" y="36.5">0.1u</text>
<text x="259.1" y="36.5">0.1u</text>
<text x="45.3" y="46.7">U7</text>
<text x="69.8" y="42.9">GND</text>
<text x="83.4" y="46.7">U8</text>
<text x="107.9" y="42.9">GND</text>
<text x="122.8" y="46.7">U9</text>
<text x="147.3" y="42.9">GND</text>
<text x="178" y="45.4">+3V3</text>
<text x="239.3" y="46.7">GND</text>
<text x="41.4" y="49.2">TSSP58038</text>
<text x="69.8" y="53">+3V3</text>
<text x="79.5" y="49.2">TSSP58038</text>
<text x="107.9" y="53">+3V3</text>
<text x="118.8" y="49.2">TSSP58038</text>
<text x="147.3" y="53">+3V3</text>
<text x="245.3" y="50.5">+3V3 +3V3</text>
<text x="174.6" y="58.1">10K</text>
<text x="175.4" y="55.6">R3</text>
<text x="69.8" y="63.2">GND</text>
<text x="107.9" y="63.2">GND</text>
<text x="147.3" y="63.2">GND</text>
<text x="202.8" y="65.7">22p</text>
<text x="203.3" y="63.2">C5</text>
<text x="219.4" y="64.4">10K</text>
<text x="219.8" y="61.9">R4</text>
<text x="41.4" y="69.5">TSSP58038</text>
<text x="44.9" y="67">U10</text>
<text x="79.5" y="69.5">TSSP58038</text>
<text x="83.2" y="67">U11</text>
<text x="118.8" y="69.5">TSSP58038</text>
<text x="122.4" y="67">U12</text>
<text x="181.6" y="69.5">SW2</text>
<text x="208.1" y="68.3">GND</text>
<text x="69.8" y="73.3">+3V3</text>
<text x="107.9" y="73.3">+3V3</text>
<text x="147.3" y="73.3">+3V3</text>
<text x="181.6" y="72.1">SW_Push</text>
<text x="187.8" y="74.6">GND</text>
<text x="215" y="75.9">8Mhz</text>
<text x="217.7" y="73.3">Y1</text>
<text x="69.8" y="83.5">GND</text>
<text x="107.9" y="83.5">GND</text>
<text x="147.3" y="83.5">GND</text>
<text x="175.4" y="81">R5</text>
<text x="175.7" y="83.5">1K</text>
<text x="202.8" y="83.5">22p</text>
<text x="208.1" y="81">GND</text>
<text x="41.4" y="89.8">TSSP58038</text>
<text x="44.9" y="87.3">U13</text>
<text x="79.5" y="89.8">TSSP58038</text>
<text x="83" y="87.3">U14</text>
<text x="118.8" y="89.8">TSSP58038</text>
<text x="122.4" y="87.3">U15</text>
<text x="203.3" y="86">C6</text>
<text x="218.9" y="84.8">LED</text>
<text x="219.5" y="87.3">D2</text>
<text x="69.8" y="93.7">+3V3</text>
<text x="107.9" y="93.7">+3V3</text>
<text x="147.3" y="93.7">+3V3</text>
<text x="178.3" y="93.7">GND</text>
<text x="69.8" y="103.8">GND</text>
<text x="107.9" y="103.8">GND</text>
<text x="147.3" y="103.8">GND</text>
<text x="41.4" y="111.4">TSSP58038</text>
<text x="44.9" y="108.9">U16</text>
<text x="79.5" y="111.4">TSSP58038</text>
<text x="83" y="108.9">U17</text>
<text x="118.8" y="111.4">TSSP58038</text>
<text x="122.4" y="108.9">U18</text>
<text x="69.8" y="115.2">+3V3</text>
<text x="107.9" y="115.2">+3V3</text>
<text x="147.3" y="115.2">+3V3</text>
<text x="69.8" y="125.4">GND</text>
<text x="107.9" y="125.4">GND</text>
<text x="147.3" y="125.4">GND</text>
<text x="41.4" y="131.8">TSSP58038</text>
<text x="44.9" y="129.2">U19</text>
<text x="79.5" y="131.8">TSSP58038</text>
<text x="82.8" y="129.2">U20</text>
<text x="118.8" y="131.8">TSSP58038</text>
<text x="122.4" y="129.2">U21</text>
<text x="69.8" y="135.6">+3V3</text>
<text x="107.9" y="135.6">+3V3</text>
<text x="147.3" y="135.6">+3V3</text>
<text x="252.6" y="136.8">IC1</text>
<text x="226.3" y="143.2">J3</text>
<text x="252.6" y="139.4">STM32F103CBTx</text>
<text x="44.7" y="149.5">U22</text>
<text x="69.8" y="145.7">GND</text>
<text x="82.8" y="149.5">U23</text>
<text x="107.9" y="145.7">GND</text>
<text x="122.2" y="149.5">U24</text>
<text x="147.3" y="145.7">GND</text>
<text x="222" y="145.7">Conn_01x04</text>
<text x="243.8" y="149.5">GND</text>
<text x="246.9" y="145.7">GND</text>
<text x="41.4" y="152.1">TSSP58038</text>
<text x="69.8" y="155.9">+3V3</text>
<text x="79.5" y="152.1">TSSP58038</text>
<text x="107.9" y="155.9">+3V3</text>
<text x="118.8" y="152.1">TSSP58038</text>
<text x="147.3" y="155.9">+3V3</text>
<text x="243.8" y="157.2">+3V3</text>
<text x="69.8" y="166">GND</text>
<text x="107.9" y="166">GND</text>
<text x="147.3" y="166">GND</text>
<text x="41.4" y="172.4">TSSP58038</text>
<text x="44.7" y="169.9">U25</text>
<text x="79.5" y="172.4">TSSP58038</text>
<text x="82.8" y="169.9">U26</text>
<text x="118.8" y="172.4">TSSP58038</text>
<text x="122.2" y="169.9">U27</text>
<text x="69.8" y="176.2">+3V3</text>
<text x="107.9" y="176.2">+3V3</text>
<text x="147.3" y="176.2">+3V3</text>
<text x="69.8" y="186.4">GND</text>
<text x="107.9" y="186.4">GND</text>
<text x="147.3" y="186.4">GND</text>
</g>
<g font-size="1.8" fill="#434c5e">
<text x="52.9" y="32.7">Vs</text>
<text x="56.6" y="31.5">3</text>
<text x="91" y="32.7">Vs</text>
<text x="94.7" y="31.5">3</text>
<text x="130.3" y="32.7">Vs</text>
<text x="134.1" y="31.5">3</text>
<text x="51" y="37.8">OUT</text>
<text x="56.6" y="41.7">2</text>
<text x="56.8" y="36.6">1</text>
<text x="59.7" y="36.5">IR1</text>
<text x="89.1" y="37.8">OUT</text>
<text x="94.7" y="41.7">2</text>
<text x="94.9" y="36.6">1</text>
<text x="97.8" y="36.5">IR2</text>
<text x="128.5" y="37.8">OUT</text>
<text x="134.1" y="41.7">2</text>
<text x="134.2" y="36.6">1</text>
<text x="137.2" y="36.5">IR3</text>
<text x="50.9" y="42.9">GND</text>
<text x="89" y="42.9">GND</text>
<text x="128.3" y="42.9">GND</text>
<text x="52.9" y="53">Vs</text>
<text x="56.6" y="51.8">3</text>
<text x="91" y="53">Vs</text>
<text x="94.7" y="51.8">3</text>
<text x="130.3" y="53">Vs</text>
<text x="134.1" y="51.8">3</text>
<text x="51" y="58.1">OUT</text>
<text x="56.8" y="56.9">1</text>
<text x="59.7" y="56.8">IR4</text>
<text x="89.1" y="58.1">OUT</text>
<text x="94.9" y="56.9">1</text>
<text x="97.8" y="56.8">IR5</text>
<text x="128.5" y="58.1">OUT</text>
<text x="134.2" y="56.9">1</text>
<text x="137.2" y="56.8">IR6</text>
<text x="244.9" y="58.8" transform="rotate(-90 244.9 58.8)">1</text>
<text x="247.4" y="59.6" transform="rotate(-90 247.4 59.6)">24</text>
<text x="249.9" y="59.6" transform="rotate(-90 249.9 59.6)">36</text>
<text x="252.5" y="59.6" transform="rotate(-90 252.5 59.6)">48</text>
<text x="255" y="59" transform="rotate(-90 255 59)">9</text>
<text x="50.9" y="63.2">GND</text>
<text x="56.6" y="62">2</text>
<text x="89" y="63.2">GND</text>
<text x="94.7" y="62">2</text>
<text x="128.3" y="63.2">GND</text>
<text x="134.1" y="62">2</text>
<text x="184.1" y="61.9">RST</text>
<text x="226.1" y="61.9">RST</text>
<text x="233.1" y="62">7</text>
<text x="235.5" y="63.2">NRST</text>
<text x="246.1" y="64.9" transform="rotate(-90 246.1 64.9)">VBAT</text>
<text x="248.6" y="63.9" transform="rotate(-90 248.6 63.9)">VDD</text>
<text x="251.1" y="63.9" transform="rotate(-90 251.1 63.9)">VDD</text>
<text x="253.7" y="63.9" transform="rotate(-90 253.7 63.9)">VDD</text>
<text x="256.2" y="65.2" transform="rotate(-90 256.2 65.2)">VDDA</text>
<text x="258.9" y="63.2">PA0</text>
<text x="259.3" y="65.7">PA1</text>
<text x="263.2" y="62">10</text>
<text x="263.4" y="64.5">11</text>
<text x="266.5" y="61.9">IR20</text>
<text x="266.8" y="64.4">IR21</text>
<text x="226.1" y="67">BOOT</text>
<text x="232.5" y="67.1">44</text>
<text x="235.5" y="68.3">BOOT0</text>
<text x="258.9" y="68.3">PA2</text>
<text x="258.9" y="70.8">PA3</text>
<text x="263.2" y="67.1">12</text>
<text x="263.2" y="69.6">13</text>
<text x="266.5" y="69.5">IR23</text>
<text x="266.5" y="67">IR22</text>
<text x="52.9" y="73.3">Vs</text>
<text x="56.6" y="72.1">3</text>
<text x="56.8" y="77.2">1</text>
<text x="59.7" y="77.1">IR7</text>
<text x="91" y="73.3">Vs</text>
<text x="94.7" y="72.1">3</text>
<text x="94.9" y="77.2">1</text>
<text x="97.8" y="77.1">IR8</text>
<text x="130.3" y="73.3">Vs</text>
<text x="134.1" y="72.1">3</text>
<text x="134.2" y="77.2">1</text>
<text x="137.2" y="77.1">IR9</text>
<text x="233.1" y="72.1">5</text>
<text x="233.1" y="74.7">6</text>
<text x="235.5" y="73.3">PD0</text>
<text x="235.5" y="75.9">PD1</text>
<text x="258.9" y="73.3">PA4</text>
<text x="258.9" y="75.9">PA5</text>
<text x="263.2" y="72.1">14</text>
<text x="263.2" y="74.7">15</text>
<text x="263.2" y="77.2">16</text>
<text x="266.5" y="72">IR24</text>
<text x="267.6" y="77.1">IR2</text>
<text x="268" y="74.6">IR1</text>
<text x="50.9" y="83.5">GND</text>
<text x="51" y="78.4">OUT</text>
<text x="56.6" y="82.3">2</text>
<text x="89" y="83.5">GND</text>
<text x="89.1" y="78.4">OUT</text>
<text x="94.7" y="82.3">2</text>
<text x="128.3" y="83.5">GND</text>
<text x="128.5" y="78.4">OUT</text>
<text x="134.1" y="82.3">2</text>
<text x="233.1" y="79.8">2</text>
<text x="233.1" y="82.3">3</text>
<text x="235.5" y="81">PC13</text>
<text x="235.5" y="83.5">PC14</text>
<text x="258.9" y="78.4">PA6</text>
<text x="258.9" y="81">PA7</text>
<text x="258.9" y="83.5">PA8</text>
<text x="263" y="82.3">29</text>
<text x="263.2" y="79.8">17</text>
<text x="267.6" y="82.2">IR9</text>
<text x="267.6" y="79.7">IR3</text>
<text x="227.3" y="89.8">IR4</text>
<text x="232.7" y="89.9">18</text>
<text x="233.1" y="84.8">4</text>
<text x="235.5" y="86">PC15</text>
<text x="258.1" y="88.6">PA10</text>
<text x="258.9" y="86">PA9</text>
<text x="263" y="84.8">30</text>
<text x="263" y="89.9">32</text>
<text x="263.2" y="87.4">31</text>
<text x="266.7" y="84.7">IR RX</text>
<text x="266.7" y="87.3">IR TX</text>
<text x="266.8" y="89.8">IR10</text>
<text x="52.9" y="93.7">Vs</text>
<text x="56.6" y="92.5">3</text>
<text x="91" y="93.7">Vs</text>
<text x="94.7" y="92.5">3</text>
<text x="130.3" y="93.7">Vs</text>
<text x="134.1" y="92.5">3</text>
<text x="227.3" y="92.4">IR5</text>
<text x="227.3" y="94.9">IR6</text>
<text x="232.5" y="95">20</text>
<text x="232.7" y="92.5">19</text>
<text x="235.5" y="91.1">PB0</text>
<text x="235.5" y="93.7">PB1</text>
<text x="258.1" y="93.7">PA12</text>
<text x="258.5" y="91.1">PA11</text>
<text x="263" y="92.5">33</text>
<text x="263" y="95">34</text>
<text x="266.7" y="94.9">SWDIO</text>
<text x="267.2" y="92.4">IR11</text>
<text x="51" y="98.7">OUT</text>
<text x="56.8" y="97.5">1</text>
<text x="59.7" y="97.4">IR10</text>
<text x="89.1" y="98.7">OUT</text>
<text x="94.9" y="97.5">1</text>
<text x="97.8" y="97.4">IR11</text>
<text x="128.5" y="98.7">OUT</text>
<text x="134.2" y="97.5">1</text>
<text x="137.2" y="97.4">IR12</text>
<text x="227.3" y="97.4">IR13</text>
<text x="227.3" y="100">IR14</text>
<text x="232.5" y="97.5">39</text>
<text x="232.5" y="100.1">40</text>
<text x="235.5" y="96.2">PB2</text>
<text x="235.5" y="98.7">PB3</text>
<text x="235.5" y="101.3">PB4</text>
<text x="258.1" y="96.2">PA13</text>
<text x="258.1" y="98.7">PA14</text>
<text x="258.1" y="101.3">PA15</text>
<text x="263" y="100.1">38</text>
<text x="263.1" y="97.5">37</text>
<text x="266.7" y="97.4">SWCLK</text>
<text x="266.8" y="100">IR12</text>
<text x="50.9" y="103.8">GND</text>
<text x="56.6" y="102.6">2</text>
<text x="89" y="103.8">GND</text>
<text x="94.7" y="102.6">2</text>
<text x="128.3" y="103.8">GND</text>
<text x="134.1" y="102.6">2</text>
<text x="227.3" y="102.5">IR15</text>
<text x="227.3" y="105.1">IR16</text>
<text x="227.3" y="107.6">IR17</text>
<text x="232.5" y="105.2">42</text>
<text x="232.5" y="107.7">43</text>
<text x="232.7" y="102.6">41</text>
<text x="235.5" y="103.8">PB5</text>
<text x="235.5" y="106.4">PB6</text>
<text x="227.3" y="112.7">IR19</text>
<text x="227.5" y="110.1">IR18</text>
<text x="232.5" y="110.2">45</text>
<text x="232.5" y="112.8">46</text>
<text x="235.5" y="108.9">PB7</text>
<text x="235.5" y="111.4">PB8</text>
<text x="235.5" y="114">PB9</text>
<text x="52.9" y="115.2">Vs</text>
<text x="56.6" y="114">3</text>
<text x="56.8" y="119.1">1</text>
<text x="59.7" y="119">IR13</text>
<text x="91" y="115.2">Vs</text>
<text x="94.7" y="114">3</text>
<text x="94.9" y="119.1">1</text>
<text x="97.8" y="119">IR14</text>
<text x="130.3" y="115.2">Vs</text>
<text x="134.1" y="114">3</text>
<text x="134.2" y="119.1">1</text>
<text x="137.2" y="119">IR15</text>
<text x="232.5" y="117.9">22</text>
<text x="232.7" y="115.3">21</text>
<text x="235.5" y="116.5">PB10</text>
<text x="235.5" y="119.1">PB11</text>
<text x="50.9" y="125.4">GND</text>
<text x="51" y="120.3">OUT</text>
<text x="56.6" y="124.2">2</text>
<text x="89" y="125.4">GND</text>
<text x="89.1" y="120.3">OUT</text>
<text x="94.7" y="124.2">2</text>
<text x="128.3" y="125.4">GND</text>
<text x="128.5" y="120.3">OUT</text>
<text x="134.1" y="124.2">2</text>
<text x="227.3" y="125.4">IR8</text>
<text x="232.5" y="120.4">25</text>
<text x="232.5" y="122.9">26</text>
<text x="232.6" y="125.5">27</text>
<text x="235.5" y="121.6">PB12</text>
<text x="235.5" y="124.1">PB13</text>
<text x="227.3" y="127.9">IR7</text>
<text x="232.5" y="128">28</text>
<text x="235.5" y="126.7">PB14</text>
<text x="235.5" y="129.2">PB15</text>
<text x="52.9" y="135.6">Vs</text>
<text x="56.6" y="134.4">3</text>
<text x="91" y="135.6">Vs</text>
<text x="94.7" y="134.4">3</text>
<text x="130.3" y="135.6">Vs</text>
<text x="134.1" y="134.4">3</text>
<text x="247.4" y="135.8" transform="rotate(-90 247.4 135.8)">23</text>
<text x="248.6" y="132.8" transform="rotate(-90 248.6 132.8)">VSS</text>
<text x="249.9" y="135.2" transform="rotate(-90 249.9 135.2)">8</text>
<text x="251.1" y="132.8" transform="rotate(-90 251.1 132.8)">VSSA</text>
<text x="51" y="140.6">OUT</text>
<text x="56.8" y="139.4">1</text>
<text x="59.7" y="139.4">IR16</text>
<text x="89.1" y="140.6">OUT</text>
<text x="94.9" y="139.4">1</text>
<text x="97.8" y="139.4">IR17</text>
<text x="128.5" y="140.6">OUT</text>
<text x="134.2" y="139.4">1</text>
<text x="137.2" y="139.4">IR18</text>
<text x="50.9" y="145.7">GND</text>
<text x="56.6" y="144.5">2</text>
<text x="89" y="145.7">GND</text>
<text x="94.7" y="144.5">2</text>
<text x="128.3" y="145.7">GND</text>
<text x="134.1" y="144.5">2</text>
<text x="230.1" y="148.3">1</text>
<text x="52.9" y="155.9">Vs</text>
<text x="56.6" y="154.7">3</text>
<text x="91" y="155.9">Vs</text>
<text x="94.7" y="154.7">3</text>
<text x="130.3" y="155.9">Vs</text>
<text x="134.1" y="154.7">3</text>
<text x="229.9" y="150.9">2</text>
<text x="229.9" y="153.4">3</text>
<text x="229.9" y="156">4</text>
<text x="233.7" y="153.3">SWCLK</text>
<text x="233.7" y="150.8">SWDIO</text>
<text x="51" y="161">OUT</text>
<text x="56.8" y="159.8">1</text>
<text x="59.7" y="159.7">IR19</text>
<text x="89.1" y="161">OUT</text>
<text x="94.9" y="159.8">1</text>
<text x="97.8" y="159.7">IR20</text>
<text x="128.5" y="161">OUT</text>
<text x="134.2" y="159.8">1</text>
<text x="137.2" y="159.7">IR21</text>
<text x="50.9" y="166">GND</text>
<text x="56.6" y="164.8">2</text>
<text x="89" y="166">GND</text>
<text x="94.7" y="164.8">2</text>
<text x="128.3" y="166">GND</text>
<text x="134.1" y="164.8">2</text>
<text x="52.9" y="176.2">Vs</text>
<text x="56.6" y="175">3</text>
<text x="59.7" y="180">IR22</text>
<text x="91" y="176.2">Vs</text>
<text x="94.7" y="175">3</text>
<text x="97.8" y="180">IR23</text>
<text x="130.3" y="176.2">Vs</text>
<text x="134.1" y="175">3</text>
<text x="137.2" y="180">IR24</text>
<text x="51" y="181.3">OUT</text>
<text x="56.6" y="185.2">2</text>
<text x="56.8" y="180.1">1</text>
<text x="89.1" y="181.3">OUT</text>
<text x="94.7" y="185.2">2</text>
<text x="94.9" y="180.1">1</text>
<text x="128.5" y="181.3">OUT</text>
<text x="134.1" y="185.2">2</text>
<text x="134.2" y="180.1">1</text>
<text x="50.9" y="186.4">GND</text>
<text x="89" y="186.4">GND</text>
<text x="128.3" y="186.4">GND</text>
</g>
<g font-size="1.8" fill="#bf616a">
<text x="275.8" y="88.7">IR TX</text>
<text x="275.8" y="86.1">IR RX</text>
</g>
</g></defs>
<path d="M0 0h297v210h-297z" fill="#eceff4" stroke="#eceff4" stroke-width=".18"/>
<g fill="none" stroke="#3b4252" stroke-width=".18">
<path d="M10 10h277v190h-277zM12 12h273v186h-273zM60 10v2M110 10v2M160 10v2M210 10v2M260 10v2M10 60h2M285 60h2M10 110h2M285 110h2M10 160h2"/>
<path d="M285 160h2M177 166h108v32h-108zM60 198v2M110 198v2M160 198v2M177 194.5h108M177 191.5h108M177 187.5h108M177 181.5h108M197 191.5v3M210 198v2M260 198v2"/>
<path d="M261 191.5v6.5"/>
</g>
<g fill="none" stroke="#4c566a" stroke-width=".18">
<path d="M180.3 47l-.7 1.3M180.3 47v2.5M180.3 47l.8 1.3M66 62.2h1.3v-1.2l1.3 1.2-1.3 1.3v-1.3M143.5 62.2h1.3v-1.2l1.2 1.2-1.2 1.3v-1.3M116.1 96.5l.9 .9M116.2 97.5l.9 .9M116.5 97.4h.5M116.6 98.4h.5M117 96.9v.5M117.1 97.9v.5M117.3 98.8h1.7"/>
<path d="M119.6 92.2h6.3v11.2h-6.3zM119.6 96.4h-1.5v3.2h1.5M125.9 92.7h1.7M127 93.3h1.3v3.2h-1.3zM127 99.7v1.9M127.6 96.5v1.3M128.3 92.7h-.7v.6M128.3 97.8h-.7v1.9l-.6 .6M133.3 92.7h2.6M133.3 97.8h2.6M143.5 92.7h2.5M144.8 91.9l1.2 .8"/>
<path d="M146 92.7l-1.2 .8M125.9 102.9h1.7M125.9 100.7h1.1M127 101l.6 .6v1.3h.7M127.4 101.1v.2h-.3M133.3 102.9h2.6M143.5 102.9h1.3v-1.3l1.2 1.3-1.2 1.2v-1.2M66 134.6h2.6M67.3 133.9l1.3 .7M68.6 134.6l-1.3 .8"/>
</g>
<g fill="#e5e9f0" stroke="#e5e9f0" stroke-width=".18">
<path d="M115.3 96.6l.1-.2 1.2 1.6-1.2 1.6a1.97 1.97 0 0 1-.1-3z"/>
<path d="M115.6 91.4h17.7v12.7h-17.7z"/>
</g>
<path d="M115.4 96.4a1.97 1.97 0 0 0 0 3.2M115.6 91.4h17.7v12.7h-17.7z" fill="none" stroke="#4c566a" stroke-width=".25"/>
<path d="M117.3 97.2h1.7l-.9 1.6z" fill="#4c566a" stroke="#4c566a" stroke-width=".18"/>
<path d="M128.2 88.2l.4-.1 .4 .2v.3l-.2 .1 .3 .4-.2 .3h-.5l-.3-.2v-.1l.5 .2 .3-.2-.1-.2-.2-.1-.5 .3 .2-.4-.1-.2 .3 .2 .3-.2-.2-.2-.4 .2z" fill="#5e81ac"/>
<g fill="#e5e9f0" stroke="#e5e9f0" stroke-width=".18">
<path d="M37.8 138.5l.2-.2 1.1 1.6-1.1 1.6a1.97 1.97 0 0 1-.2-3z"/>
<path d="M38.1 133.4h17.8v12.7h-17.8z"/>
</g>
<path d="M38 138.3a1.97 1.97 0 0 0 0 3.2M38.1 133.4h17.8v12.7h-17.8z" fill="none" stroke="#4c566a" stroke-width=".25"/>
<g fill="none" stroke="#4c566a" stroke-width=".18">
<path d="M38.6 138.4l.9 .9M38.7 139.4l.9 .9M39 139.3h.5M39.5 138.8v.5M39.6 139.8v.5M42.2 134.1h6.2v11.2h-6.2zM42.2 138.3h-1.6v3.2h1.6M48.4 134.6h1.8M49.5 135.3h1.3v3.1h-1.3zM50.2 138.4v1.3M50.8 134.6h-.6v.7M50.8 139.7h-.6v1.9l-.7 .6"/>
<path d="M55.9 134.6h2.5M55.9 139.7h2.5M39.1 140.3h.5M39.9 140.7h1.6M48.4 144.8h1.8M48.4 142.6h1.1M49.5 142.9l.7 .6v1.3h.6M49.5 141.6v1.9M49.9 143v.3h-.2M55.9 144.8h2.5"/>
</g>
<path d="M39.9 139.1h1.6l-.9 1.6z" fill="#4c566a" stroke="#4c566a" stroke-width=".18"/>
<path d="M50.8 130.1l.4-.1 .3 .2v.3l-.2 .1 .3 .4-.2 .3h-.4l-.3-.1-.1-.2 .5 .2 .3-.2v-.2l-.3-.1-.5 .3 .3-.4-.2-.2 .4 .2 .3-.2-.2-.2-.5 .2z" fill="#5e81ac"/>
<g fill="none" stroke="#4c566a" stroke-width=".18">
<path d="M177.3 69.9h1.8M179.1 67.3v5.1M180.3 64.8v2.5M180.3 72.4v2.5M180.3 87.6v1.3h1.3l-1.3 1.3-1.2-1.3h1.2M116.1 158.8l.9 .8M116.2 159.8l.9 .9M116.5 159.6h.5M117 159.1v.5M119.6 154.4h6.3v11.2h-6.3zM119.6 158.6h-1.5v3.2h1.5M125.9 154.9h1.7"/>
<path d="M127 155.6h1.3v3.2h-1.3zM127.6 158.8v1.2M128.3 154.9h-.7v.7M133.3 154.9h2.6M116.6 160.7h.5M117.1 160.1v.6M117.3 161h1.7M125.9 165.1h1.7M125.9 162.9h1.1M127 163.2l.6 .6v1.3h.7M127 161.9v1.9M127.4 163.3v.3h-.3"/>
<path d="M128.3 160h-.7v1.9l-.6 .7M133.3 165.1h2.6M133.3 160h2.6"/>
<circle cx="180.3" cy="67.8" r=".51"/>
<circle cx="180.3" cy="71.9" r=".51"/>
</g>
<g fill="#e5e9f0" stroke="#e5e9f0" stroke-width=".18">
<path d="M115.3 158.8l.1-.2 1.2 1.6-1.2 1.6a1.97 1.97 0 0 1-.1-3z"/>
<path d="M115.6 153.7h17.7v12.7h-17.7z"/>
</g>
<path d="M115.4 158.6a1.97 1.97 0 0 0 0 3.2M115.6 153.7h17.7v12.7h-17.7z" fill="none" stroke="#4c566a" stroke-width=".25"/>
<path d="M117.3 159.4h1.7l-.9 1.6z" fill="#4c566a" stroke="#4c566a" stroke-width=".18"/>
<path d="M128.2 150.5l.4-.2 .4 .2v.3l-.2 .2 .3 .3-.2 .3-.5 .1-.3-.2v-.2l.5 .2 .3-.2-.1-.2-.2-.1-.5 .3 .2-.3-.1-.3 .3 .2 .3-.2-.2-.2-.4 .2z" fill="#5e81ac"/>
<g fill="#e5e9f0" stroke="#e5e9f0" stroke-width=".18">
<path d="M115.3 179.1l.1-.2 1.2 1.6-1.2 1.6a1.97 1.97 0 0 1-.1-3z"/>
<path d="M115.6 174h17.7v12.7h-17.7z"/>
</g>
<path d="M115.4 178.9a1.97 1.97 0 0 0 0 3.2M115.6 174h17.7v12.7h-17.7z" fill="none" stroke="#4c566a" stroke-width=".25"/>
<g fill="none" stroke="#4c566a" stroke-width=".18">
<path d="M116.1 179.1l.9 .9M116.5 180h.5M117 179.5v.5M119.6 174.8h6.3v11.1h-6.3zM119.6 178.9h-1.5v3.2h1.5M125.9 175.3h1.7M127 175.9h1.3v3.2h-1.3zM127.6 179.1v1.2M128.3 175.3h-.7v.6M133.3 175.3h2.6M116.2 180.1l.9 .9M116.6 181h.5"/>
<path d="M117.1 180.5v.5M117.3 181.4h1.7M125.9 185.4h1.7M125.9 183.3h1.1M127 183.5l.6 .7v1.2h.7M127 182.2v2M127.4 183.6v.3h-.3M128.3 180.3h-.7v1.9l-.6 .7M133.3 185.4h2.6M133.3 180.3h2.6"/>
</g>
<path d="M117.3 179.7h1.7l-.9 1.7z" fill="#4c566a" stroke="#4c566a" stroke-width=".18"/>
<path d="M128.2 170.8l.4-.1 .4 .1v.3l-.2 .2 .3 .4-.2 .2-.5 .1-.3-.2v-.2l.5 .3 .3-.3-.1-.2h-.2l-.5 .2 .2-.3-.1-.3 .3 .2 .3-.1-.2-.3-.4 .2z" fill="#5e81ac"/>
<g fill="none" stroke="#4c566a" stroke-width=".18">
<path d="M194.3 73.7v-1.3l-1.3 1.3 1.3 1.2v-1.2h1.3M76.7 138.4l.9 .9M76.8 139.4l.9 .9M77.1 139.3h.5M77.6 138.8v.5M77.7 139.8v.5M80.3 134.1h6.2v11.2h-6.2zM80.3 138.3h-1.6v3.2h1.6M86.5 134.6h1.8M87.6 135.3h1.3v3.1h-1.3zM88.3 138.4v1.3M88.9 134.6h-.6v.7"/>
<path d="M88.9 139.7h-.6v1.9l-.7 .6M94 134.6h2.5M94 139.7h2.5M104.1 124.5h1.3v-1.3l1.3 1.3-1.3 1.2v-1.2M104.1 134.6h2.6M105.4 133.9l1.3 .7M106.7 134.6l-1.3 .8M143.5 134.6h2.5M144.8 133.9l1.2 .7M146 134.6l-1.2 .8M77.2 140.3h.5M78 140.7h1.6"/>
<path d="M86.5 144.8h1.8M86.5 142.6h1.1M87.6 142.9l.7 .6v1.3h.6M87.6 141.6v1.9M88 143v.3h-.2M94 144.8h2.5M143.5 144.8h1.3v-1.3l1.2 1.3-1.2 1.3v-1.3M143.5 154.9h2.5M144.8 154.2l1.2 .7M146 154.9l-1.2 .8"/>
</g>
<g fill="#e5e9f0" stroke="#e5e9f0" stroke-width=".18">
<path d="M75.9 138.5l.2-.2 1.1 1.6-1.1 1.6a1.97 1.97 0 0 1-.2-3z"/>
<path d="M76.2 133.4h17.8v12.7h-17.8z"/>
</g>
<path d="M76.1 138.3a1.97 1.97 0 0 0 0 3.2M76.2 133.4h17.8v12.7h-17.8z" fill="none" stroke="#4c566a" stroke-width=".25"/>
<path d="M78 139.1h1.6l-.9 1.6z" fill="#4c566a" stroke="#4c566a" stroke-width=".18"/>
<path d="M88.9 130.1l.4-.1 .3 .2v.3l-.2 .1 .3 .4-.2 .3h-.4l-.3-.1-.1-.2 .5 .2 .3-.2v-.2l-.3-.1-.5 .3 .3-.4-.2-.2 .4 .2 .3-.2-.2-.2-.5 .2z" fill="#5e81ac"/>
<g fill="#e5e9f0" stroke="#e5e9f0" stroke-width=".18">
<path d="M75.9 118.1l.2-.1 1.1 1.6-1.1 1.6a1.97 1.97 0 0 1-.2-3.1z"/>
<path d="M76.2 113h17.8v12.7h-17.8z"/>
</g>
<path d="M76.1 118a1.97 1.97 0 0 0 0 3.2M76.2 113h17.8v12.7h-17.8z" fill="none" stroke="#4c566a" stroke-width=".25"/>
<g fill="none" stroke="#4c566a" stroke-width=".18">
<path d="M76.7 118.1l.9 .9M76.8 119.1l.9 .9M77.1 119h.5M77.6 118.5v.5M77.7 119.5v.5M80.3 113.8h6.2v11.2h-6.2zM80.3 118h-1.6v3.2h1.6M86.5 114.3h1.8M87.6 114.9h1.3v3.2h-1.3zM88.3 118.1v1.3M88.9 114.3h-.6v.6M88.9 119.4h-.6v1.9l-.7 .6"/>
<path d="M94 114.3h2.5M94 119.4h2.5M77.2 120h.5M78 120.4h1.6M86.5 124.5h1.8M86.5 122.3h1.1M87.6 122.6l.7 .6v1.3h.6M87.6 121.3v1.9M88 122.7v.2h-.2M94 124.5h2.5"/>
</g>
<path d="M78 118.7h1.6l-.9 1.7z" fill="#4c566a" stroke="#4c566a" stroke-width=".18"/>
<path d="M88.9 109.8l.4-.1 .3 .2v.2l-.2 .2 .3 .4-.2 .3h-.4l-.3-.2-.1-.2 .5 .3 .3-.2v-.2l-.3-.1-.5 .2 .3-.3-.2-.3 .4 .3 .3-.2-.2-.3-.5 .2z" fill="#5e81ac"/>
<g fill="none" stroke="#4c566a" stroke-width=".18">
<path d="M104.1 114.3h2.6M105.4 113.5l1.3 .8M106.7 114.3l-1.3 .8M116.1 118.1l.9 .9M116.2 119.1l.9 .9M116.5 119h.5M117 118.5v.5M117.1 119.5v.5M119.6 113.8h6.3v11.2h-6.3zM119.6 118h-1.5v3.2h1.5M125.9 114.3h1.7M127 114.9h1.3v3.2h-1.3z"/>
<path d="M127.6 118.1v1.3M128.3 114.3h-.7v.6M128.3 119.4h-.7v1.9l-.6 .6M133.3 114.3h2.6M133.3 119.4h2.6M143.5 114.3h2.5M144.8 113.5l1.2 .8M146 114.3l-1.2 .8M116.6 120h.5M117.3 120.4h1.7M125.9 124.5h1.7M125.9 122.3h1.1"/>
<path d="M127 122.6l.6 .6v1.3h.7M127 121.3v1.9M127.4 122.7v.2h-.3M133.3 124.5h2.6M143.5 124.5h1.3v-1.3l1.2 1.3-1.2 1.2v-1.2"/>
</g>
<g fill="#e5e9f0" stroke="#e5e9f0" stroke-width=".18">
<path d="M115.3 118.1l.1-.1 1.2 1.6-1.2 1.6a1.97 1.97 0 0 1-.1-3.1z"/>
<path d="M115.6 113h17.7v12.7h-17.7z"/>
</g>
<path d="M115.4 118a1.97 1.97 0 0 0 0 3.2M115.6 113h17.7v12.7h-17.7z" fill="none" stroke="#4c566a" stroke-width=".25"/>
<path d="M117.3 118.7h1.7l-.9 1.7z" fill="#4c566a" stroke="#4c566a" stroke-width=".18"/>
<path d="M128.2 109.8l.4-.1 .4 .2v.2l-.2 .2 .3 .4-.2 .3h-.5l-.3-.2v-.2l.5 .3 .3-.2-.1-.2-.2-.1-.5 .2 .2-.3-.1-.3 .3 .3 .3-.2-.2-.3-.4 .2z" fill="#5e81ac"/>
<path d="M179.3 53.3h2.1v5.1h-2.1zM38 118a1.97 1.97 0 0 0 0 3.2M38.1 113h17.8v12.7h-17.8z" fill="none" stroke="#4c566a" stroke-width=".25"/>
<g fill="none" stroke="#4c566a" stroke-width=".18">
<path d="M180.3 52.1v1.2M180.3 58.4v1.3M200.7 77.5h2.8M205.5 77.5h2.8M66 92.7h2.6M67.3 91.9l1.3 .8M68.6 92.7l-1.3 .8M38.6 118.1l.9 .9M38.7 119.1l.9 .9M39 119h.5M39.5 118.5v.5M39.6 119.5v.5"/>
<path d="M42.2 113.8h6.2v11.2h-6.2zM42.2 118h-1.6v3.2h1.6M48.4 114.3h1.8M49.5 114.9h1.3v3.2h-1.3zM50.2 118.1v1.3M50.8 114.3h-.6v.6M50.8 119.4h-.6v1.9l-.7 .6M55.9 114.3h2.5M55.9 119.4h2.5M39.1 120h.5M39.9 120.4h1.6M48.4 124.5h1.8"/>
<path d="M48.4 122.3h1.1M49.5 122.6l.7 .6v1.3h.6M49.5 121.3v1.9M49.9 122.7v.2h-.2M55.9 124.5h2.5M66 124.5h1.3v-1.3l1.3 1.3-1.3 1.2v-1.2M143.5 165.1h1.3v-1.3l1.2 1.3-1.2 1.3v-1.3M143.5 175.3h2.5M144.8 174.5l1.2 .8M146 175.3l-1.2 .7M143.5 185.4h1.3v-1.2l1.2 1.2-1.2 1.3v-1.3"/>
</g>
<path d="M203.7 75.4v4.1M205.2 75.4v4.1" fill="none" stroke="#4c566a" stroke-width=".51"/>
<g fill="#e5e9f0" stroke="#e5e9f0" stroke-width=".18">
<path d="M37.8 118.1l.2-.1 1.1 1.6-1.1 1.6a1.97 1.97 0 0 1-.2-3.1z"/>
<path d="M38.1 113h17.8v12.7h-17.8z"/>
</g>
<path d="M39.9 118.7h1.6l-.9 1.7z" fill="#4c566a" stroke="#4c566a" stroke-width=".18"/>
<path d="M50.8 109.8l.4-.1 .3 .2v.2l-.2 .2 .3 .4-.2 .3h-.4l-.3-.2-.1-.2 .5 .3 .3-.2v-.2l-.3-.1-.5 .2 .3-.3-.2-.3 .4 .3 .3-.2-.2-.3-.5 .2z" fill="#5e81ac"/>
<g fill="none" stroke="#4c566a" stroke-width=".18">
<path d="M143.5 82.6h1.3v-1.3l1.2 1.3-1.2 1.2v-1.2M66 114.3h2.6M67.3 113.5l1.3 .8M68.6 114.3l-1.3 .8M116.1 138.4l.9 .9M116.2 139.4l.9 .9M116.5 139.3h.5M117 138.8v.5M117.1 139.8v.5M119.6 134.1h6.3v11.2h-6.3zM119.6 138.3h-1.5v3.2h1.5M125.9 134.6h1.7"/>
<path d="M127 135.3h1.3v3.1h-1.3zM127.6 138.4v1.3M128.3 134.6h-.7v.7M128.3 139.7h-.7v1.9l-.6 .6M133.3 134.6h2.6M133.3 139.7h2.6M116.6 140.3h.5M117.3 140.7h1.7M125.9 144.8h1.7M125.9 142.6h1.1M127 142.9l.6 .6v1.3h.7M127 141.6v1.9"/>
<path d="M127.4 143v.3h-.3M133.3 144.8h2.6"/>
</g>
<g fill="#e5e9f0" stroke="#e5e9f0" stroke-width=".18">
<path d="M115.3 138.5l.1-.2 1.2 1.6-1.2 1.6a1.97 1.97 0 0 1-.1-3z"/>
<path d="M115.6 133.4h17.7v12.7h-17.7z"/>
</g>
<path d="M115.4 138.3a1.97 1.97 0 0 0 0 3.2M115.6 133.4h17.7v12.7h-17.7z" fill="none" stroke="#4c566a" stroke-width=".25"/>
<path d="M117.3 139.1h1.7l-.9 1.6z" fill="#4c566a" stroke="#4c566a" stroke-width=".18"/>
<path d="M128.2 130.1l.4-.1 .4 .2v.3l-.2 .1 .3 .4-.2 .3h-.5l-.3-.1v-.2l.5 .2 .3-.2-.1-.2-.2-.1-.5 .3 .2-.4-.1-.2 .3 .2 .3-.2-.2-.2-.4 .2z" fill="#5e81ac"/>
<g fill="none" stroke="#4c566a" stroke-width=".18">
<path d="M247.6 52.1l-.7 1.2M247.6 52.1v2.5M247.6 52.1l.8 1.2M66 72.4h2.6M67.3 71.6l1.3 .8M68.6 72.4l-1.3 .8M76.7 76.2l.9 .9M76.8 77.2l.9 .9M77.1 77.1h.5M77.2 78.1h.5M77.6 76.6v.5M77.7 77.6v.5"/>
<path d="M78 78.5h1.6M80.3 71.9h6.2v11.2h-6.2zM80.3 76.1h-1.6v3.1h1.6M86.5 72.4h1.8M87.6 73h1.3v3.2h-1.3zM87.6 79.4v1.9M88.3 76.2v1.3M88.9 72.4h-.6v.6M88.9 77.5h-.6v1.9l-.7 .6M94 72.4h2.5M94 77.5h2.5M66 82.6h1.3v-1.3l1.3 1.3-1.3 1.2v-1.2"/>
<path d="M86.5 82.6h1.8M86.5 80.4h1.1M87.6 80.6l.7 .7v1.3h.6M88 80.8v.2h-.2M94 82.6h2.5M214.6 80v-1.3l-1.2 1.3 1.2 1.3v-1.3h1.3M66 102.9h1.3v-1.3l1.3 1.3-1.3 1.2v-1.2M227.3 156.1h1.3v.2h-1.3zM227.3 153.5h1.3v.3h-1.3zM227.3 151h1.3v.3h-1.3zM227.3 148.5h1.3v.2h-1.3zM228.6 148.6h3.8"/>
<path d="M228.6 151.1h3.8M228.6 153.7h3.8M228.6 156.2h3.8"/>
</g>
<g fill="#e5e9f0" stroke="#e5e9f0" stroke-width=".18">
<path d="M226.1 147.3h2.5v10.2h-2.5z"/>
<path d="M75.9 76.2l.2-.1 1.1 1.6-1.1 1.5a1.97 1.97 0 0 1-.2-3z"/>
<path d="M76.2 71.1h17.8v12.7h-17.8z"/>
</g>
<path d="M76.1 76.1a1.97 1.97 0 0 0 0 3.1M76.2 71.1h17.8v12.7h-17.8zM226.1 147.3h2.5v10.2h-2.5z" fill="none" stroke="#4c566a" stroke-width=".25"/>
<path d="M78 76.8h1.6l-.9 1.7z" fill="#4c566a" stroke="#4c566a" stroke-width=".18"/>
<path d="M88.9 67.9l.4-.1 .3 .2v.2l-.2 .2 .3 .4-.2 .3h-.4l-.3-.2-.1-.2 .5 .3 .3-.2v-.2l-.3-.1-.5 .2 .3-.3-.2-.3 .4 .3 .3-.2-.2-.3-.5 .2z" fill="#5e81ac"/>
<g fill="#e5e9f0" stroke="#e5e9f0" stroke-width=".18">
<path d="M75.9 96.6l.2-.2 1.1 1.6-1.1 1.6a1.97 1.97 0 0 1-.2-3z"/>
<path d="M76.2 91.4h17.8v12.7h-17.8z"/>
</g>
<path d="M76.1 96.4a1.97 1.97 0 0 0 0 3.2M76.2 91.4h17.8v12.7h-17.8z" fill="none" stroke="#4c566a" stroke-width=".25"/>
<g fill="none" stroke="#4c566a" stroke-width=".18">
<path d="M76.7 96.5l.9 .9M76.8 97.5l.9 .9M77.1 97.4h.5M77.2 98.4h.5M77.6 96.9v.5M77.7 97.9v.5M78 98.8h1.6M80.3 92.2h6.2v11.2h-6.2zM80.3 96.4h-1.6v3.2h1.6M86.5 92.7h1.8M87.6 93.3h1.3v3.2h-1.3zM87.6 99.7v1.9"/>
<path d="M88.3 96.5v1.3M88.9 92.7h-.6v.6M88.9 97.8h-.6v1.9l-.7 .6M94 92.7h2.5M94 97.8h2.5M86.5 102.9h1.8M86.5 100.7h1.1M87.6 101l.7 .6v1.3h.6M88 101.1v.2h-.2M94 102.9h2.5"/>
</g>
<path d="M78 97.2h1.6l-.9 1.6z" fill="#4c566a" stroke="#4c566a" stroke-width=".18"/>
<path d="M88.9 88.2l.4-.1 .3 .2v.3l-.2 .1 .3 .4-.2 .3h-.4l-.3-.2-.1-.1 .5 .2 .3-.2v-.2l-.3-.1-.5 .3 .3-.4-.2-.2 .4 .2 .3-.2-.2-.2-.5 .2z" fill="#5e81ac"/>
<g fill="none" stroke="#4c566a" stroke-width=".18">
<path d="M217.2 67.3h1.2M223.5 67.3h1.3M38.6 96.5l.9 .9M38.7 97.5l.9 .9M39 97.4h.5M39.1 98.4h.5M39.5 96.9v.5M39.6 97.9v.5M39.9 98.8h1.6M42.2 92.2h6.2v11.2h-6.2zM42.2 96.4h-1.6v3.2h1.6M48.4 92.7h1.8"/>
<path d="M49.5 93.3h1.3v3.2h-1.3zM49.5 99.7v1.9M50.2 96.5v1.3M50.8 92.7h-.6v.6M50.8 97.8h-.6v1.9l-.7 .6M55.9 92.7h2.5M55.9 97.8h2.5M48.4 102.9h1.8M48.4 100.7h1.1M49.5 101l.7 .6v1.3h.6M49.9 101.1v.2h-.2M55.9 102.9h2.5"/>
<path d="M104.1 102.9h1.3v-1.3l1.3 1.3-1.3 1.2v-1.2M240 148.6h1.3v1.3l1.3-1.3-1.3-1.3v1.3M240 156.2h2.6M241.3 155.4l1.3 .8M242.6 156.2l-1.3 .8"/>
</g>
<path d="M218.4 66.3h5.1v2h-5.1zM38 96.4a1.97 1.97 0 0 0 0 3.2M38.1 91.4h17.8v12.7h-17.8z" fill="none" stroke="#4c566a" stroke-width=".25"/>
<g fill="#e5e9f0" stroke="#e5e9f0" stroke-width=".18">
<path d="M37.8 96.6l.2-.2 1.1 1.6-1.1 1.6a1.97 1.97 0 0 1-.2-3z"/>
<path d="M38.1 91.4h17.8v12.7h-17.8z"/>
</g>
<path d="M39.9 97.2h1.6l-.9 1.6z" fill="#4c566a" stroke="#4c566a" stroke-width=".18"/>
<path d="M50.8 88.2l.4-.1 .3 .2v.3l-.2 .1 .3 .4-.2 .3h-.4l-.3-.2-.1-.1 .5 .2 .3-.2v-.2l-.3-.1-.5 .3 .3-.4-.2-.2 .4 .2 .3-.2-.2-.2-.5 .2z" fill="#5e81ac"/>
<g fill="none" stroke="#4c566a" stroke-width=".18">
<path d="M38.6 35.6l.9 .8M38.7 36.6l.9 .9M39 36.4h.5M39.1 37.5h.5M39.5 35.9v.5M39.6 37v.5M39.9 37.8h1.6M42.2 31.2h6.2v11.2h-6.2zM42.2 35.4h-1.6v3.2h1.6M48.4 31.8h1.8M48.4 39.8h1.1M49.5 32.4h1.3v3.2h-1.3z"/>
<path d="M49.5 38.7v1.9M50.2 35.6v1.2M50.8 31.8h-.6v.6M50.8 36.8h-.6v1.9l-.7 .7M55.9 31.8h2.5M55.9 36.8h2.5M48.4 41.9h1.8M49.5 40l.7 .6v1.3h.6M49.9 40.1v.3h-.2M55.9 41.9h2.5M66 52.1h2.6M67.3 51.3l1.3 .8"/>
<path d="M68.6 52.1l-1.3 .7M180.3 77.5v1.2M104.1 92.7h2.6M105.4 91.9l1.3 .8M106.7 92.7l-1.3 .8M180.3 83.8v1.3M248.9 139.7v1.3h1.3l-1.3 1.2-1.3-1.2h1.3"/>
</g>
<path d="M38 35.4a1.97 1.97 0 0 0 0 3.2M38.1 30.5h17.8v12.7h-17.8zM179.3 78.7h2.1v5.1h-2.1z" fill="none" stroke="#4c566a" stroke-width=".25"/>
<g fill="#e5e9f0" stroke="#e5e9f0" stroke-width=".18">
<path d="M37.8 35.6l.2-.2 1.1 1.6-1.1 1.6a1.97 1.97 0 0 1-.2-3z"/>
<path d="M38.1 30.5h17.8v12.7h-17.8z"/>
</g>
<path d="M39.9 36.2h1.6l-.9 1.6z" fill="#4c566a" stroke="#4c566a" stroke-width=".18"/>
<path d="M50.8 27.3l.4-.1 .3 .1v.3l-.2 .2 .3 .3-.2 .3-.4 .1-.3-.2-.1-.2 .5 .2 .3-.2v-.2h-.3l-.5 .2 .3-.3-.2-.3 .4 .2 .3-.2-.2-.2-.5 .2z" fill="#5e81ac"/>
<g fill="#e5e9f0" stroke="#e5e9f0" stroke-width=".18">
<path d="M37.8 55.9l.2-.1 1.1 1.5-1.1 1.6a1.97 1.97 0 0 1-.2-3z"/>
<path d="M38.1 50.8h17.8v12.7h-17.8z"/>
</g>
<path d="M38 55.8a1.97 1.97 0 0 0 0 3.1M38.1 50.8h17.8v12.7h-17.8z" fill="none" stroke="#4c566a" stroke-width=".25"/>
<g fill="none" stroke="#4c566a" stroke-width=".18">
<path d="M38.6 55.9l.9 .9M38.7 56.9l.9 .9M39 56.8h.5M39.1 57.8h.5M39.5 56.3v.5M39.6 57.3v.5M39.9 58.2h1.6M42.2 51.6h6.2v11.1h-6.2zM42.2 55.8h-1.6v3.1h1.6M48.4 52.1h1.8M49.5 52.7h1.3v3.2h-1.3zM49.5 59.1v1.9"/>
<path d="M50.2 55.9v1.3M50.8 52.1h-.6v.6M50.8 57.2h-.6v1.9l-.7 .6M55.9 52.1h2.5M55.9 57.2h2.5M48.4 62.2h1.8M48.4 60.1h1.1M49.5 60.3l.7 .7v1.2h.6M49.9 60.5v.2h-.2M55.9 62.2h2.5"/>
</g>
<path d="M39.9 56.5h1.6l-.9 1.7z" fill="#4c566a" stroke="#4c566a" stroke-width=".18"/>
<path d="M50.8 47.6l.4-.1 .3 .2v.2l-.2 .2 .3 .4-.2 .2-.4 .1-.3-.2-.1-.2 .5 .3 .3-.3v-.2h-.3l-.5 .2 .3-.3-.2-.3 .4 .2 .3-.1-.2-.3-.5 .2z" fill="#5e81ac"/>
<g fill="none" stroke="#4c566a" stroke-width=".18">
<path d="M143.5 41.9h1.3v-1.3l1.2 1.3-1.2 1.3v-1.3M38.6 76.2l.9 .9M38.7 77.2l.9 .9M39 77.1h.5M39.1 78.1h.5M39.5 76.6v.5M39.6 77.6v.5M39.9 78.5h1.6M42.2 71.9h6.2v11.2h-6.2zM42.2 76.1h-1.6v3.1h1.6M48.4 72.4h1.8M49.5 73h1.3v3.2h-1.3z"/>
<path d="M49.5 79.4v1.9M50.2 76.2v1.3M50.8 72.4h-.6v.6M50.8 77.5h-.6v1.9l-.7 .6M55.9 72.4h2.5M55.9 77.5h2.5M104.1 72.4h2.6M105.4 71.6l1.3 .8M106.7 72.4l-1.3 .8M48.4 82.6h1.8M48.4 80.4h1.1M49.5 80.6l.7 .7v1.3h.6"/>
<path d="M49.9 80.8v.2h-.2M55.9 82.6h2.5M104.1 82.6h1.3v-1.3l1.3 1.3-1.3 1.2v-1.2"/>
</g>
<g fill="#e5e9f0" stroke="#e5e9f0" stroke-width=".18">
<path d="M37.8 76.2l.2-.1 1.1 1.6-1.1 1.5a1.97 1.97 0 0 1-.2-3z"/>
<path d="M38.1 71.1h17.8v12.7h-17.8z"/>
</g>
<path d="M38 76.1a1.97 1.97 0 0 0 0 3.1M38.1 71.1h17.8v12.7h-17.8z" fill="none" stroke="#4c566a" stroke-width=".25"/>
<path d="M39.9 76.8h1.6l-.9 1.7z" fill="#4c566a" stroke="#4c566a" stroke-width=".18"/>
<path d="M50.8 67.9l.4-.1 .3 .2v.2l-.2 .2 .3 .4-.2 .3h-.4l-.3-.2-.1-.2 .5 .3 .3-.2v-.2l-.3-.1-.5 .2 .3-.3-.2-.3 .4 .3 .3-.2-.2-.3-.5 .2z" fill="#5e81ac"/>
<g fill="#e5e9f0" stroke="#e5e9f0" stroke-width=".18">
<path d="M234.9 59.7h28v73.7h-28z"/>
<path d="M75.9 35.6l.2-.2 1.1 1.6-1.1 1.6a1.97 1.97 0 0 1-.2-3z"/>
<path d="M76.2 30.5h17.8v12.7h-17.8z"/>
</g>
<path d="M76.1 35.4a1.97 1.97 0 0 0 0 3.2M76.2 30.5h17.8v12.7h-17.8zM234.9 59.7h28v73.7h-28z" fill="none" stroke="#4c566a" stroke-width=".25"/>
<g fill="none" stroke="#4c566a" stroke-width=".18">
<path d="M76.7 35.6l.9 .8M76.8 36.6l.9 .9M77.1 36.4h.5M77.2 37.5h.5M77.6 35.9v.5M77.7 37v.5M78 37.8h1.6M80.3 31.2h6.2v11.2h-6.2zM80.3 35.4h-1.6v3.2h1.6M86.5 31.8h1.8M86.5 39.8h1.1M87.6 32.4h1.3v3.2h-1.3z"/>
<path d="M87.6 38.7v1.9M88.3 35.6v1.2M88.9 31.8h-.6v.6M88.9 36.8h-.6v1.9l-.7 .7M94 31.8h2.5M94 36.8h2.5M86.5 41.9h1.8M87.6 40l.7 .6v1.3h.6M88 40.1v.3h-.2M94 41.9h2.5M245.1 57.2v2.5M255.3 57.2v2.5"/>
<path d="M232.4 72.4h2.5M232.4 74.9h2.5M232.4 62.2h2.5M262.9 64.8h2.5M232.4 80h2.5M232.4 82.6h2.5M232.4 85.1h2.5M262.9 87.6h2.5M232.4 115.6h2.5M232.4 102.9h2.5M250.2 133.4v2.5"/>
</g>
<path d="M78 36.2h1.6l-.9 1.6z" fill="#4c566a" stroke="#4c566a" stroke-width=".18"/>
<path d="M88.9 27.3l.4-.1 .3 .1v.3l-.2 .2 .3 .3-.2 .3-.4 .1-.3-.2-.1-.2 .5 .2 .3-.2v-.2h-.3l-.5 .2 .3-.3-.2-.3 .4 .2 .3-.2-.2-.2-.5 .2z" fill="#5e81ac"/>
<g fill="none" stroke="#4c566a" stroke-width=".18">
<path d="M66 31.8h2.6M67.3 31l1.3 .8M68.6 31.8l-1.3 .7M66 41.9h1.3v-1.3l1.3 1.3-1.3 1.3v-1.3M76.7 55.9l.9 .9M76.8 56.9l.9 .9M77.1 56.8h.5M77.2 57.8h.5M77.6 56.3v.5M77.7 57.3v.5M78 58.2h1.6M80.3 51.6h6.2v11.1h-6.2z"/>
<path d="M80.3 55.8h-1.6v3.1h1.6M86.5 52.1h1.8M87.6 52.7h1.3v3.2h-1.3zM87.6 59.1v1.9M88.3 55.9v1.3M88.9 52.1h-.6v.6M88.9 57.2h-.6v1.9l-.7 .6M94 52.1h2.5M94 57.2h2.5M86.5 62.2h1.8M86.5 60.1h1.1M87.6 60.3l.7 .7v1.2h.6"/>
<path d="M88 60.5v.2h-.2M94 62.2h2.5"/>
</g>
<g fill="#e5e9f0" stroke="#e5e9f0" stroke-width=".18">
<path d="M75.9 55.9l.2-.1 1.1 1.5-1.1 1.6a1.97 1.97 0 0 1-.2-3z"/>
<path d="M76.2 50.8h17.8v12.7h-17.8z"/>
</g>
<path d="M76.1 55.8a1.97 1.97 0 0 0 0 3.1M76.2 50.8h17.8v12.7h-17.8z" fill="none" stroke="#4c566a" stroke-width=".25"/>
<path d="M78 56.5h1.6l-.9 1.7z" fill="#4c566a" stroke="#4c566a" stroke-width=".18"/>
<path d="M88.9 47.6l.4-.1 .3 .2v.2l-.2 .2 .3 .4-.2 .2-.4 .1-.3-.2-.1-.2 .5 .3 .3-.3v-.2h-.3l-.5 .2 .3-.3-.2-.3 .4 .2 .3-.1-.2-.3-.5 .2z" fill="#5e81ac"/>
<path d="M115.4 55.8a1.97 1.97 0 0 0 0 3.1M115.6 50.8h17.7v12.7h-17.7zM221 78.7v2.6M221 80l2.5-1.3v2.6z" fill="none" stroke="#4c566a" stroke-width=".25"/>
<g fill="none" stroke="#4c566a" stroke-width=".18">
<path d="M143.5 31.8h2.5M144.8 31l1.2 .8M146 31.8l-1.2 .7M104.1 52.1h2.6M105.4 51.3l1.3 .8M106.7 52.1l-1.3 .7M116.1 55.9l.9 .9M116.2 56.9l.9 .9M116.5 56.8h.5M116.6 57.8h.5M117 56.3v.5M117.1 57.3v.5"/>
<path d="M117.3 58.2h1.7M119.6 51.6h6.3v11.1h-6.3zM119.6 55.8h-1.5v3.1h1.5M125.9 52.1h1.7M127 52.7h1.3v3.2h-1.3zM127 59.1v1.9M127.6 55.9v1.3M128.3 52.1h-.7v.6M128.3 57.2h-.7v1.9l-.6 .6M133.3 52.1h2.6M133.3 57.2h2.6M104.1 62.2h1.3v-1.2l1.3 1.2-1.3 1.3v-1.3"/>
<path d="M125.9 62.2h1.7M125.9 60.1h1.1M127 60.3l.6 .7v1.2h.7M127.4 60.5v.2h-.3M133.3 62.2h2.6M217.7 78.5v-.8h.7h-.7l1.5 1.5M218.9 78.5v-.8h.8h-.8l1.6 1.5M218.4 80h7.7M104.1 144.8h1.3v-1.3l1.3 1.3-1.3 1.3v-1.3"/>
</g>
<g fill="#e5e9f0" stroke="#e5e9f0" stroke-width=".18">
<path d="M115.3 55.9l.1-.1 1.2 1.5-1.2 1.6a1.97 1.97 0 0 1-.1-3z"/>
<path d="M115.6 50.8h17.7v12.7h-17.7z"/>
</g>
<path d="M117.3 56.5h1.7l-.9 1.7z" fill="#4c566a" stroke="#4c566a" stroke-width=".18"/>
<path d="M128.2 47.6l.4-.1 .4 .2v.2l-.2 .2 .3 .4-.2 .2-.5 .1-.3-.2v-.2l.5 .3 .3-.3-.1-.2h-.2l-.5 .2 .2-.3-.1-.3 .3 .2 .3-.1-.2-.3-.4 .2z" fill="#5e81ac"/>
<g fill="none" stroke="#4c566a" stroke-width=".18">
<path d="M200.7 69.9h2.8M205.5 69.9h2.8M214.6 67.3v-1.3l-1.2 1.3 1.2 1.3v-1.3h1.3M223.5 69.9v1.9M223.5 75.6v1.9M38.6 179.1l.9 .9M39 180h.5M39.5 179.5v.5M42.2 174.8h6.2v11.1h-6.2zM42.2 178.9h-1.6v3.2h1.6M48.4 175.3h1.8M49.5 175.9h1.3v3.2h-1.3z"/>
<path d="M50.2 179.1v1.2M50.8 175.3h-.6v.6M55.9 175.3h2.5M38.7 180.1l.9 .9M39.1 181h.5M39.6 180.5v.5M39.9 181.4h1.6M48.4 185.4h1.8M48.4 183.3h1.1M49.5 183.5l.7 .7v1.2h.6M49.5 182.2v2M49.9 183.6v.3h-.2"/>
<path d="M50.8 180.3h-.6v1.9l-.7 .7M55.9 185.4h2.5M55.9 180.3h2.5"/>
</g>
<path d="M203.7 67.8v4.1M205.2 67.8v4.1M222.2 75.6h2.6M222.2 71.8h2.6" fill="none" stroke="#4c566a" stroke-width=".51"/>
<path d="M221 72.5h5.1v2.3h-5.1z" fill="none" stroke="#4c566a" stroke-width=".3"/>
<g fill="#e5e9f0" stroke="#e5e9f0" stroke-width=".18">
<path d="M37.8 179.1l.2-.2 1.1 1.6-1.1 1.6a1.97 1.97 0 0 1-.2-3z"/>
<path d="M38.1 174h17.8v12.7h-17.8z"/>
</g>
<path d="M38 178.9a1.97 1.97 0 0 0 0 3.2M38.1 174h17.8v12.7h-17.8z" fill="none" stroke="#4c566a" stroke-width=".25"/>
<path d="M39.9 179.7h1.6l-.9 1.7z" fill="#4c566a" stroke="#4c566a" stroke-width=".18"/>
<path d="M50.8 170.8l.4-.1 .3 .1v.3l-.2 .2 .3 .4-.2 .2-.4 .1-.3-.2-.1-.2 .5 .3 .3-.3v-.2h-.3l-.5 .2 .3-.3-.2-.3 .4 .2 .3-.1-.2-.3-.5 .2z" fill="#5e81ac"/>
<g fill="none" stroke="#4c566a" stroke-width=".18">
<path d="M104.1 31.8h2.6M105.4 31l1.3 .8M106.7 31.8l-1.3 .7M104.1 41.9h1.3v-1.3l1.3 1.3-1.3 1.3v-1.3M143.5 52.1h2.5M144.8 51.3l1.2 .8M146 52.1l-1.2 .7M66 175.3h2.6M67.3 174.5l1.3 .8M68.6 175.3l-1.3 .7M76.7 179.1l.9 .9M77.1 180h.5"/>
<path d="M77.6 179.5v.5M80.3 174.8h6.2v11.1h-6.2zM80.3 178.9h-1.6v3.2h1.6M86.5 175.3h1.8M87.6 175.9h1.3v3.2h-1.3zM88.3 179.1v1.2M88.9 175.3h-.6v.6M94 175.3h2.5M66 185.4h1.3v-1.2l1.3 1.2-1.3 1.3v-1.3M76.8 180.1l.9 .9M77.2 181h.5M77.7 180.5v.5"/>
<path d="M78 181.4h1.6M86.5 185.4h1.8M86.5 183.3h1.1M87.6 183.5l.7 .7v1.2h.6M87.6 182.2v2M88 183.6v.3h-.2M88.9 180.3h-.6v1.9l-.7 .7M94 185.4h2.5M94 180.3h2.5M104.1 185.4h1.3v-1.2l1.3 1.2-1.3 1.3v-1.3"/>
</g>
<g fill="#e5e9f0" stroke="#e5e9f0" stroke-width=".18">
<path d="M75.9 179.1l.2-.2 1.1 1.6-1.1 1.6a1.97 1.97 0 0 1-.2-3z"/>
<path d="M76.2 174h17.8v12.7h-17.8z"/>
</g>
<path d="M76.1 178.9a1.97 1.97 0 0 0 0 3.2M76.2 174h17.8v12.7h-17.8z" fill="none" stroke="#4c566a" stroke-width=".25"/>
<path d="M78 179.7h1.6l-.9 1.7z" fill="#4c566a" stroke="#4c566a" stroke-width=".18"/>
<path d="M88.9 170.8l.4-.1 .3 .1v.3l-.2 .2 .3 .4-.2 .2-.4 .1-.3-.2-.1-.2 .5 .3 .3-.3v-.2h-.3l-.5 .2 .3-.3-.2-.3 .4 .2 .3-.1-.2-.3-.5 .2z" fill="#5e81ac"/>
<g fill="#e5e9f0" stroke="#e5e9f0" stroke-width=".18">
<path d="M115.3 35.6l.1-.2 1.2 1.6-1.2 1.6a1.97 1.97 0 0 1-.1-3z"/>
<path d="M115.6 30.5h17.7v12.7h-17.7z"/>
</g>
<path d="M115.4 35.4a1.97 1.97 0 0 0 0 3.2M115.6 30.5h17.7v12.7h-17.7z" fill="none" stroke="#4c566a" stroke-width=".25"/>
<g fill="none" stroke="#4c566a" stroke-width=".18">
<path d="M116.1 35.6l.9 .8M116.2 36.6l.9 .9M116.5 36.4h.5M116.6 37.5h.5M117 35.9v.5M117.1 37v.5M117.3 37.8h1.7M119.6 31.2h6.3v11.2h-6.3zM119.6 35.4h-1.5v3.2h1.5M125.9 31.8h1.7M125.9 39.8h1.1M127 32.4h1.3v3.2h-1.3z"/>
<path d="M127 38.7v1.9M127.6 35.6v1.2M128.3 31.8h-.7v.6M128.3 36.8h-.7v1.9l-.6 .7M133.3 31.8h2.6M133.3 36.8h2.6M125.9 41.9h1.7M127 40l.6 .6v1.3h.7M127.4 40.1v.3h-.3M133.3 41.9h2.6"/>
</g>
<path d="M117.3 36.2h1.7l-.9 1.6z" fill="#4c566a" stroke="#4c566a" stroke-width=".18"/>
<path d="M128.2 27.3l.4-.1 .4 .1v.3l-.2 .2 .3 .3-.2 .3-.5 .1-.3-.2v-.2l.5 .2 .3-.2-.1-.2h-.2l-.5 .2 .2-.3-.1-.3 .3 .2 .3-.2-.2-.2-.4 .2z" fill="#5e81ac"/>
<g fill="none" stroke="#4c566a" stroke-width=".18">
<path d="M224.8 30.5v2.8M224.8 35.3v2.8M250.2 52.1l-.8 1.2M250.2 52.1v2.5M250.2 52.1l.8 1.2M116.1 76.2l.9 .9M116.2 77.2l.9 .9M116.5 77.1h.5M116.6 78.1h.5M117 76.6v.5M117.1 77.6v.5M117.3 78.5h1.7"/>
<path d="M119.6 71.9h6.3v11.2h-6.3zM119.6 76.1h-1.5v3.1h1.5M125.9 72.4h1.7M127 73h1.3v3.2h-1.3zM127 79.4v1.9M127.6 76.2v1.3M128.3 72.4h-.7v.6M128.3 77.5h-.7v1.9l-.6 .6M133.3 72.4h2.6M133.3 77.5h2.6M125.9 82.6h1.7M125.9 80.4h1.1"/>
<path d="M127 80.6l.6 .7v1.3h.7M127.4 80.8v.2h-.3M133.3 82.6h2.6M104.1 175.3h2.6M105.4 174.5l1.3 .8M106.7 175.3l-1.3 .7"/>
</g>
<path d="M222.8 35.1h4M222.8 33.5h4" fill="none" stroke="#4c566a" stroke-width=".51"/>
<g fill="#e5e9f0" stroke="#e5e9f0" stroke-width=".18">
<path d="M115.3 76.2l.1-.1 1.2 1.6-1.2 1.5a1.97 1.97 0 0 1-.1-3z"/>
<path d="M115.6 71.1h17.7v12.7h-17.7z"/>
</g>
<path d="M115.4 76.1a1.97 1.97 0 0 0 0 3.1M115.6 71.1h17.7v12.7h-17.7z" fill="none" stroke="#4c566a" stroke-width=".25"/>
<path d="M117.3 76.8h1.7l-.9 1.7z" fill="#4c566a" stroke="#4c566a" stroke-width=".18"/>
<path d="M128.2 67.9l.4-.1 .4 .2v.2l-.2 .2 .3 .4-.2 .3h-.5l-.3-.2v-.2l.5 .3 .3-.2-.1-.2-.2-.1-.5 .2 .2-.3-.1-.3 .3 .3 .3-.2-.2-.3-.4 .2z" fill="#5e81ac"/>
<g fill="none" stroke="#4c566a" stroke-width=".18">
<path d="M38.6 158.8l.9 .8M38.7 159.8l.9 .9M39 159.6h.5M39.5 159.1v.5M42.2 154.4h6.2v11.2h-6.2zM42.2 158.6h-1.6v3.2h1.6M48.4 154.9h1.8M49.5 155.6h1.3v3.2h-1.3zM50.2 158.8v1.2M50.8 154.9h-.6v.7M55.9 154.9h2.5M66 154.9h2.6"/>
<path d="M67.3 154.2l1.3 .7M68.6 154.9l-1.3 .8M39.1 160.7h.5M39.6 160.1v.6M39.9 161h1.6M48.4 165.1h1.8M48.4 162.9h1.1M49.5 163.2l.7 .6v1.3h.6M49.5 161.9v1.9M49.9 163.3v.3h-.2M50.8 160h-.6v1.9l-.7 .7M55.9 165.1h2.5"/>
<path d="M55.9 160h2.5"/>
</g>
<g fill="#e5e9f0" stroke="#e5e9f0" stroke-width=".18">
<path d="M37.8 158.8l.2-.2 1.1 1.6-1.1 1.6a1.97 1.97 0 0 1-.2-3z"/>
<path d="M38.1 153.7h17.8v12.7h-17.8z"/>
</g>
<path d="M38 158.6a1.97 1.97 0 0 0 0 3.2M38.1 153.7h17.8v12.7h-17.8z" fill="none" stroke="#4c566a" stroke-width=".25"/>
<path d="M39.9 159.4h1.6l-.9 1.6z" fill="#4c566a" stroke="#4c566a" stroke-width=".18"/>
<path d="M50.8 150.5l.4-.2 .3 .2v.3l-.2 .2 .3 .3-.2 .3-.4 .1-.3-.2-.1-.2 .5 .2 .3-.2v-.2l-.3-.1-.5 .3 .3-.3-.2-.3 .4 .2 .3-.2-.2-.2-.5 .2z" fill="#5e81ac"/>
<path d="M232.9 35.1h4.1M232.9 33.5h4.1M253.2 35.1h4.1M253.2 33.5h4.1" fill="none" stroke="#4c566a" stroke-width=".51"/>
<g fill="none" stroke="#4c566a" stroke-width=".18">
<path d="M234.9 30.5v2.8M234.9 35.3v2.8M241.3 25.4l-.8 1.3M241.3 25.4v2.5M241.3 25.4l.8 1.3M255.3 30.5v2.8M255.3 35.3v2.8M143.5 72.4h2.5M144.8 71.6l1.2 .8M146 72.4l-1.2 .8M66 144.8h1.3v-1.3l1.3 1.3-1.3 1.3v-1.3M76.7 158.8l.9 .8"/>
<path d="M76.8 159.8l.9 .9M77.1 159.6h.5M77.6 159.1v.5M80.3 154.4h6.2v11.2h-6.2zM80.3 158.6h-1.6v3.2h1.6M86.5 154.9h1.8M87.6 155.6h1.3v3.2h-1.3zM88.3 158.8v1.2M88.9 154.9h-.6v.7M94 154.9h2.5M104.1 154.9h2.6M105.4 154.2l1.3 .7"/>
<path d="M106.7 154.9l-1.3 .8M66 165.1h1.3v-1.3l1.3 1.3-1.3 1.3v-1.3M77.2 160.7h.5M77.7 160.1v.6M78 161h1.6M86.5 165.1h1.8M86.5 162.9h1.1M87.6 163.2l.7 .6v1.3h.6M87.6 161.9v1.9M88 163.3v.3h-.2M88.9 160h-.6v1.9l-.7 .7M94 165.1h2.5"/>
<path d="M94 160h2.5"/>
</g>
<g fill="#e5e9f0" stroke="#e5e9f0" stroke-width=".18">
<path d="M75.9 158.8l.2-.2 1.1 1.6-1.1 1.6a1.97 1.97 0 0 1-.2-3z"/>
<path d="M76.2 153.7h17.8v12.7h-17.8z"/>
</g>
<path d="M76.1 158.6a1.97 1.97 0 0 0 0 3.2M76.2 153.7h17.8v12.7h-17.8z" fill="none" stroke="#4c566a" stroke-width=".25"/>
<path d="M78 159.4h1.6l-.9 1.6z" fill="#4c566a" stroke="#4c566a" stroke-width=".18"/>
<path d="M88.9 150.5l.4-.2 .3 .2v.3l-.2 .2 .3 .3-.2 .3-.4 .1-.3-.2-.1-.2 .5 .2 .3-.2v-.2l-.3-.1-.5 .3 .3-.3-.2-.3 .4 .2 .3-.2-.2-.2-.5 .2z" fill="#5e81ac"/>
<path d="M243.1 35.1h4M243.1 33.5h4" fill="none" stroke="#4c566a" stroke-width=".51"/>
<path d="M245.1 30.5v2.8M245.1 35.3v2.8M252.7 52.1l-.7 1.2M252.7 52.1v2.5M252.7 52.1l.8 1.2M255.3 52.1l-.8 1.2M255.3 52.1v2.5M255.3 52.1l.7 1.2M104.1 165.1h1.3v-1.3l1.3 1.3-1.3 1.3v-1.3" fill="none" stroke="#4c566a" stroke-width=".18"/>
<g fill="#5e81ac">
<path d="M255.3 48.8h.2l.3 1.1 .4-1.1h.2l-.5 1.2h-.2z"/>
<path d="M256.7 48.9l.4-.1 .3 .2v.2l-.2 .2 .2 .1 .1 .2-.2 .3-.5 .1-.2-.3-.1-.2h.2l.2 .3h.3l.1-.2-.1-.2-.3-.1v-.1l.3-.1v-.2l-.3-.1-.2 .3h-.1z"/>
</g>
<path d="M241.3 40.6v1.3h1.3l-1.3 1.3-1.3-1.3h1.3M180.3 64.8v2.5M180.3 72.4v2.5M200.7 69.9h2.8M200.7 77.5h2.8M205.5 69.9h2.8M205.5 77.5h2.8" fill="none" stroke="#4c566a" stroke-width=".18"/>
<path d="M275.4 86.4h5.7l1.1 1.2-1.1 1.3h-5.7l-1.1-1.3zM275.4 83.8h5.8l1.1 1.3-1.1 1.3h-5.8l-1.1-1.3z" fill="none" stroke="#bf616a" stroke-width=".18"/>
<g fill="none" stroke="#a3be8c" stroke-width=".18">
<path d="M58.4 36.8h7.6M58.4 31.8h7.6M96.5 36.8h7.6M96.5 31.8h7.6M135.9 36.8h7.6M135.9 31.8h7.6M224.8 38.1h30.5M224.8 30.5h30.5M241.3 27.9v2.6M241.3 38.1v2.5M58.4 57.2h7.6M58.4 41.9h7.6"/>
<path d="M58.4 52.1h7.6M96.5 57.2h7.6M96.5 41.9h7.6M96.5 52.1h7.6M135.9 57.2h7.6M135.9 41.9h7.6M135.9 52.1h7.6M180.3 49.5v2.6M180.3 59.7v5.1M247.6 55.9h7.7M247.6 54.6v2.6M250.2 54.6v2.6"/>
<path d="M252.7 54.6v2.6M255.3 54.6v2.6M58.4 62.2h7.6M58.4 77.5h7.6M58.4 72.4h7.6M96.5 62.2h7.6M96.5 77.5h7.6M96.5 72.4h7.6M135.9 62.2h7.6M135.9 77.5h7.6M135.9 72.4h7.6M180.3 62.2h10.2"/>
<path d="M180.3 74.9v2.6M195.6 73.7h2.5M200.7 69.9h-2.6v7.6h2.6M208.3 69.9h19v2.5h5.1M215.9 67.3h1.3M224.8 62.2h7.6M224.8 67.3h7.6M232.4 74.9h-5.1v2.6h-19M265.4 62.2h6.4M265.4 77.5h6.4M265.4 72.4h6.4M265.4 67.3h6.4"/>
<path d="M265.4 69.9h6.4M265.4 64.8h6.4M265.4 74.9h6.4M58.4 92.7h7.6M58.4 97.8h7.6M58.4 82.6h7.6M96.5 92.7h7.6M96.5 97.8h7.6M96.5 82.6h7.6M135.9 92.7h7.6M135.9 97.8h7.6M135.9 82.6h7.6"/>
<path d="M180.3 85.1v2.5M215.9 80h2.5M226.1 92.7h6.3M226.1 97.8h6.3M226.1 95.3h6.3M226.1 90.2h6.3M226.1 80h6.3M265.4 92.7h6.4M265.4 97.8h8.9M265.4 82.6h6.4M265.4 95.3h8.9M265.4 90.2h6.4"/>
<path d="M265.4 80h6.4M265.4 85.1h8.9M265.4 87.6h8.9M58.4 119.4h7.6M58.4 114.3h7.6M58.4 102.9h7.6M96.5 119.4h7.6M96.5 114.3h7.6M96.5 102.9h7.6M135.9 119.4h7.6M135.9 114.3h7.6M135.9 102.9h7.6"/>
<path d="M226.1 102.9h6.3M226.1 100.3h6.3M226.1 113h6.3M226.1 108h6.3M226.1 110.5h6.3M226.1 105.4h6.3M265.4 100.3h6.4M58.4 124.5h7.6M58.4 139.7h7.6M58.4 134.6h7.6M96.5 124.5h7.6M96.5 139.7h7.6"/>
<path d="M96.5 134.6h7.6M135.9 124.5h7.6M135.9 139.7h7.6M135.9 134.6h7.6M226.1 128.3h6.3M226.1 125.7h6.3M247.6 135.9v2.5h2.6v-2.5M248.9 138.4v1.3M58.4 144.8h7.6M58.4 154.9h7.6M96.5 144.8h7.6M96.5 154.9h7.6"/>
<path d="M135.9 144.8h7.6M135.9 154.9h7.6M232.4 156.2h7.6M232.4 151.1h7.6M232.4 153.7h7.6M232.4 148.6h7.6M58.4 175.3h7.6M58.4 165.1h7.6M58.4 160h7.6M96.5 175.3h7.6M96.5 165.1h7.6M96.5 160h7.6"/>
<path d="M135.9 175.3h7.6M135.9 165.1h7.6M135.9 160h7.6M58.4 180.3h7.6M58.4 185.4h7.6M96.5 180.3h7.6M96.5 185.4h7.6M135.9 180.3h7.6M135.9 185.4h7.6"/>
</g>
<path d="M244.5 56.5l1.2 1.3M245.7 56.5l-1.2 1.3M231.8 84.5l1.2 1.2M231.8 81.9l1.2 1.3M233 84.5l-1.2 1.2M233 81.9l-1.2 1.3M231.8 117.5l1.2 1.2M233 117.5l-1.2 1.2M231.8 122.6l1.2 1.2M231.8 120l1.2 1.3M233 122.6l-1.2 1.2M233 120l-1.2 1.3" fill="none" stroke="#81a1c1" stroke-width=".18"/>
<g fill="#5e81ac">
<path d="M255.3 48.8h.2l.3 1.1 .4-1.1h.2l-.5 1.2h-.2z"/>
<path d="M256.7 48.9l.4-.1 .3 .2v.2l-.2 .2 .2 .1 .1 .2-.2 .3-.5 .1-.2-.3-.1-.2h.2l.2 .3h.3l.1-.2-.1-.2-.3-.1v-.1l.3-.1v-.2l-.3-.1-.2 .3h-.1z"/>
</g>
<g fill="#a3be8c" stroke="#a3be8c" stroke-width=".18">
<circle cx="234.9" cy="38.1" r=".46"/>
<circle cx="223.5" cy="69.9" r=".46"/>
<circle cx="180.3" cy="62.2" r=".46"/>
<circle cx="223.5" cy="77.5" r=".46"/>
<circle cx="198.1" cy="73.7" r=".46"/>
<circle cx="248.9" cy="138.4" r=".46"/>
<circle cx="241.3" cy="30.5" r=".46"/>
<circle cx="241.3" cy="38.1" r=".46"/>
<circle cx="255.3" cy="55.9" r=".46"/>
<circle cx="247.6" cy="55.9" r=".46"/>
<circle cx="245.1" cy="38.1" r=".46"/>
<circle cx="245.1" cy="30.5" r=".46"/>
<circle cx="234.9" cy="30.5" r=".46"/>
<circle cx="252.7" cy="55.9" r=".46"/>
</g>
<use href="#words"/>
</svg>
